# Generated deterministically by seda-macro-lef-normalizer-v1; recipe orfs-asap7-fakeram-m4-v1.
VERSION 5.8 ;
BUSBITCHARS "[]" ;
DIVIDERCHAR "/" ;

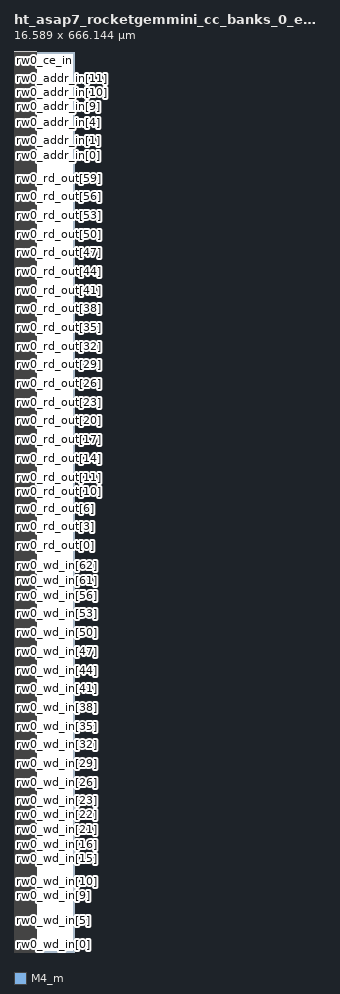
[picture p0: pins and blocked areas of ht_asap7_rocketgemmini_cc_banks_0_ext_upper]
MACRO ht_asap7_rocketgemmini_cc_banks_0_ext_upper
  FOREIGN ht_asap7_rocketgemmini_cc_banks_0_ext_upper 0 0 ;
  CLASS COVER ;
  ORIGIN 0 0 ;
  SIZE 16.589 BY 666.144 ;
  SYMMETRY X Y R90 ;
  PIN rw0_wd_in[0]
    DIRECTION INPUT ;
    USE SIGNAL ;
    SHAPE ABUTMENT ;
    PORT
      LAYER M4_m ;
      RECT 0 0.048 0.024 0.072 ;
    END
  END rw0_wd_in[0]
  PIN rw0_wd_in[1]
    DIRECTION INPUT ;
    USE SIGNAL ;
    SHAPE ABUTMENT ;
    PORT
      LAYER M4_m ;
      RECT 0 4.656 0.024 4.68 ;
    END
  END rw0_wd_in[1]
  PIN rw0_wd_in[2]
    DIRECTION INPUT ;
    USE SIGNAL ;
    SHAPE ABUTMENT ;
    PORT
      LAYER M4_m ;
      RECT 0 9.264 0.024 9.288 ;
    END
  END rw0_wd_in[2]
  PIN rw0_wd_in[3]
    DIRECTION INPUT ;
    USE SIGNAL ;
    SHAPE ABUTMENT ;
    PORT
      LAYER M4_m ;
      RECT 0 13.872 0.024 13.896 ;
    END
  END rw0_wd_in[3]
  PIN rw0_wd_in[4]
    DIRECTION INPUT ;
    USE SIGNAL ;
    SHAPE ABUTMENT ;
    PORT
      LAYER M4_m ;
      RECT 0 18.48 0.024 18.504 ;
    END
  END rw0_wd_in[4]
  PIN rw0_wd_in[5]
    DIRECTION INPUT ;
    USE SIGNAL ;
    SHAPE ABUTMENT ;
    PORT
      LAYER M4_m ;
      RECT 0 23.088 0.024 23.112 ;
    END
  END rw0_wd_in[5]
  PIN rw0_wd_in[6]
    DIRECTION INPUT ;
    USE SIGNAL ;
    SHAPE ABUTMENT ;
    PORT
      LAYER M4_m ;
      RECT 0 27.696 0.024 27.72 ;
    END
  END rw0_wd_in[6]
  PIN rw0_wd_in[7]
    DIRECTION INPUT ;
    USE SIGNAL ;
    SHAPE ABUTMENT ;
    PORT
      LAYER M4_m ;
      RECT 0 32.304 0.024 32.328 ;
    END
  END rw0_wd_in[7]
  PIN rw0_wd_in[8]
    DIRECTION INPUT ;
    USE SIGNAL ;
    SHAPE ABUTMENT ;
    PORT
      LAYER M4_m ;
      RECT 0 36.912 0.024 36.936 ;
    END
  END rw0_wd_in[8]
  PIN rw0_wd_in[9]
    DIRECTION INPUT ;
    USE SIGNAL ;
    SHAPE ABUTMENT ;
    PORT
      LAYER M4_m ;
      RECT 0 41.52 0.024 41.544 ;
    END
  END rw0_wd_in[9]
  PIN rw0_wd_in[10]
    DIRECTION INPUT ;
    USE SIGNAL ;
    SHAPE ABUTMENT ;
    PORT
      LAYER M4_m ;
      RECT 0 46.128 0.024 46.152 ;
    END
  END rw0_wd_in[10]
  PIN rw0_wd_in[11]
    DIRECTION INPUT ;
    USE SIGNAL ;
    SHAPE ABUTMENT ;
    PORT
      LAYER M4_m ;
      RECT 0 50.736 0.024 50.76 ;
    END
  END rw0_wd_in[11]
  PIN rw0_wd_in[12]
    DIRECTION INPUT ;
    USE SIGNAL ;
    SHAPE ABUTMENT ;
    PORT
      LAYER M4_m ;
      RECT 0 55.344 0.024 55.368 ;
    END
  END rw0_wd_in[12]
  PIN rw0_wd_in[13]
    DIRECTION INPUT ;
    USE SIGNAL ;
    SHAPE ABUTMENT ;
    PORT
      LAYER M4_m ;
      RECT 0 59.952 0.024 59.976 ;
    END
  END rw0_wd_in[13]
  PIN rw0_wd_in[14]
    DIRECTION INPUT ;
    USE SIGNAL ;
    SHAPE ABUTMENT ;
    PORT
      LAYER M4_m ;
      RECT 0 64.56 0.024 64.584 ;
    END
  END rw0_wd_in[14]
  PIN rw0_wd_in[15]
    DIRECTION INPUT ;
    USE SIGNAL ;
    SHAPE ABUTMENT ;
    PORT
      LAYER M4_m ;
      RECT 0 69.168 0.024 69.192 ;
    END
  END rw0_wd_in[15]
  PIN rw0_wd_in[16]
    DIRECTION INPUT ;
    USE SIGNAL ;
    SHAPE ABUTMENT ;
    PORT
      LAYER M4_m ;
      RECT 0 73.776 0.024 73.8 ;
    END
  END rw0_wd_in[16]
  PIN rw0_wd_in[17]
    DIRECTION INPUT ;
    USE SIGNAL ;
    SHAPE ABUTMENT ;
    PORT
      LAYER M4_m ;
      RECT 0 78.384 0.024 78.408 ;
    END
  END rw0_wd_in[17]
  PIN rw0_wd_in[18]
    DIRECTION INPUT ;
    USE SIGNAL ;
    SHAPE ABUTMENT ;
    PORT
      LAYER M4_m ;
      RECT 0 82.992 0.024 83.016 ;
    END
  END rw0_wd_in[18]
  PIN rw0_wd_in[19]
    DIRECTION INPUT ;
    USE SIGNAL ;
    SHAPE ABUTMENT ;
    PORT
      LAYER M4_m ;
      RECT 0 87.6 0.024 87.624 ;
    END
  END rw0_wd_in[19]
  PIN rw0_wd_in[20]
    DIRECTION INPUT ;
    USE SIGNAL ;
    SHAPE ABUTMENT ;
    PORT
      LAYER M4_m ;
      RECT 0 92.208 0.024 92.232 ;
    END
  END rw0_wd_in[20]
  PIN rw0_wd_in[21]
    DIRECTION INPUT ;
    USE SIGNAL ;
    SHAPE ABUTMENT ;
    PORT
      LAYER M4_m ;
      RECT 0 96.816 0.024 96.84 ;
    END
  END rw0_wd_in[21]
  PIN rw0_wd_in[22]
    DIRECTION INPUT ;
    USE SIGNAL ;
    SHAPE ABUTMENT ;
    PORT
      LAYER M4_m ;
      RECT 0 101.424 0.024 101.448 ;
    END
  END rw0_wd_in[22]
  PIN rw0_wd_in[23]
    DIRECTION INPUT ;
    USE SIGNAL ;
    SHAPE ABUTMENT ;
    PORT
      LAYER M4_m ;
      RECT 0 106.032 0.024 106.056 ;
    END
  END rw0_wd_in[23]
  PIN rw0_wd_in[24]
    DIRECTION INPUT ;
    USE SIGNAL ;
    SHAPE ABUTMENT ;
    PORT
      LAYER M4_m ;
      RECT 0 110.64 0.024 110.664 ;
    END
  END rw0_wd_in[24]
  PIN rw0_wd_in[25]
    DIRECTION INPUT ;
    USE SIGNAL ;
    SHAPE ABUTMENT ;
    PORT
      LAYER M4_m ;
      RECT 0 115.248 0.024 115.272 ;
    END
  END rw0_wd_in[25]
  PIN rw0_wd_in[26]
    DIRECTION INPUT ;
    USE SIGNAL ;
    SHAPE ABUTMENT ;
    PORT
      LAYER M4_m ;
      RECT 0 119.856 0.024 119.88 ;
    END
  END rw0_wd_in[26]
  PIN rw0_wd_in[27]
    DIRECTION INPUT ;
    USE SIGNAL ;
    SHAPE ABUTMENT ;
    PORT
      LAYER M4_m ;
      RECT 0 124.464 0.024 124.488 ;
    END
  END rw0_wd_in[27]
  PIN rw0_wd_in[28]
    DIRECTION INPUT ;
    USE SIGNAL ;
    SHAPE ABUTMENT ;
    PORT
      LAYER M4_m ;
      RECT 0 129.072 0.024 129.096 ;
    END
  END rw0_wd_in[28]
  PIN rw0_wd_in[29]
    DIRECTION INPUT ;
    USE SIGNAL ;
    SHAPE ABUTMENT ;
    PORT
      LAYER M4_m ;
      RECT 0 133.68 0.024 133.704 ;
    END
  END rw0_wd_in[29]
  PIN rw0_wd_in[30]
    DIRECTION INPUT ;
    USE SIGNAL ;
    SHAPE ABUTMENT ;
    PORT
      LAYER M4_m ;
      RECT 0 138.288 0.024 138.312 ;
    END
  END rw0_wd_in[30]
  PIN rw0_wd_in[31]
    DIRECTION INPUT ;
    USE SIGNAL ;
    SHAPE ABUTMENT ;
    PORT
      LAYER M4_m ;
      RECT 0 142.896 0.024 142.92 ;
    END
  END rw0_wd_in[31]
  PIN rw0_wd_in[32]
    DIRECTION INPUT ;
    USE SIGNAL ;
    SHAPE ABUTMENT ;
    PORT
      LAYER M4_m ;
      RECT 0 147.504 0.024 147.528 ;
    END
  END rw0_wd_in[32]
  PIN rw0_wd_in[33]
    DIRECTION INPUT ;
    USE SIGNAL ;
    SHAPE ABUTMENT ;
    PORT
      LAYER M4_m ;
      RECT 0 152.112 0.024 152.136 ;
    END
  END rw0_wd_in[33]
  PIN rw0_wd_in[34]
    DIRECTION INPUT ;
    USE SIGNAL ;
    SHAPE ABUTMENT ;
    PORT
      LAYER M4_m ;
      RECT 0 156.72 0.024 156.744 ;
    END
  END rw0_wd_in[34]
  PIN rw0_wd_in[35]
    DIRECTION INPUT ;
    USE SIGNAL ;
    SHAPE ABUTMENT ;
    PORT
      LAYER M4_m ;
      RECT 0 161.328 0.024 161.352 ;
    END
  END rw0_wd_in[35]
  PIN rw0_wd_in[36]
    DIRECTION INPUT ;
    USE SIGNAL ;
    SHAPE ABUTMENT ;
    PORT
      LAYER M4_m ;
      RECT 0 165.936 0.024 165.96 ;
    END
  END rw0_wd_in[36]
  PIN rw0_wd_in[37]
    DIRECTION INPUT ;
    USE SIGNAL ;
    SHAPE ABUTMENT ;
    PORT
      LAYER M4_m ;
      RECT 0 170.544 0.024 170.568 ;
    END
  END rw0_wd_in[37]
  PIN rw0_wd_in[38]
    DIRECTION INPUT ;
    USE SIGNAL ;
    SHAPE ABUTMENT ;
    PORT
      LAYER M4_m ;
      RECT 0 175.152 0.024 175.176 ;
    END
  END rw0_wd_in[38]
  PIN rw0_wd_in[39]
    DIRECTION INPUT ;
    USE SIGNAL ;
    SHAPE ABUTMENT ;
    PORT
      LAYER M4_m ;
      RECT 0 179.76 0.024 179.784 ;
    END
  END rw0_wd_in[39]
  PIN rw0_wd_in[40]
    DIRECTION INPUT ;
    USE SIGNAL ;
    SHAPE ABUTMENT ;
    PORT
      LAYER M4_m ;
      RECT 0 184.368 0.024 184.392 ;
    END
  END rw0_wd_in[40]
  PIN rw0_wd_in[41]
    DIRECTION INPUT ;
    USE SIGNAL ;
    SHAPE ABUTMENT ;
    PORT
      LAYER M4_m ;
      RECT 0 188.976 0.024 189 ;
    END
  END rw0_wd_in[41]
  PIN rw0_wd_in[42]
    DIRECTION INPUT ;
    USE SIGNAL ;
    SHAPE ABUTMENT ;
    PORT
      LAYER M4_m ;
      RECT 0 193.584 0.024 193.608 ;
    END
  END rw0_wd_in[42]
  PIN rw0_wd_in[43]
    DIRECTION INPUT ;
    USE SIGNAL ;
    SHAPE ABUTMENT ;
    PORT
      LAYER M4_m ;
      RECT 0 198.192 0.024 198.216 ;
    END
  END rw0_wd_in[43]
  PIN rw0_wd_in[44]
    DIRECTION INPUT ;
    USE SIGNAL ;
    SHAPE ABUTMENT ;
    PORT
      LAYER M4_m ;
      RECT 0 202.8 0.024 202.824 ;
    END
  END rw0_wd_in[44]
  PIN rw0_wd_in[45]
    DIRECTION INPUT ;
    USE SIGNAL ;
    SHAPE ABUTMENT ;
    PORT
      LAYER M4_m ;
      RECT 0 207.408 0.024 207.432 ;
    END
  END rw0_wd_in[45]
  PIN rw0_wd_in[46]
    DIRECTION INPUT ;
    USE SIGNAL ;
    SHAPE ABUTMENT ;
    PORT
      LAYER M4_m ;
      RECT 0 212.016 0.024 212.04 ;
    END
  END rw0_wd_in[46]
  PIN rw0_wd_in[47]
    DIRECTION INPUT ;
    USE SIGNAL ;
    SHAPE ABUTMENT ;
    PORT
      LAYER M4_m ;
      RECT 0 216.624 0.024 216.648 ;
    END
  END rw0_wd_in[47]
  PIN rw0_wd_in[48]
    DIRECTION INPUT ;
    USE SIGNAL ;
    SHAPE ABUTMENT ;
    PORT
      LAYER M4_m ;
      RECT 0 221.232 0.024 221.256 ;
    END
  END rw0_wd_in[48]
  PIN rw0_wd_in[49]
    DIRECTION INPUT ;
    USE SIGNAL ;
    SHAPE ABUTMENT ;
    PORT
      LAYER M4_m ;
      RECT 0 225.84 0.024 225.864 ;
    END
  END rw0_wd_in[49]
  PIN rw0_wd_in[50]
    DIRECTION INPUT ;
    USE SIGNAL ;
    SHAPE ABUTMENT ;
    PORT
      LAYER M4_m ;
      RECT 0 230.448 0.024 230.472 ;
    END
  END rw0_wd_in[50]
  PIN rw0_wd_in[51]
    DIRECTION INPUT ;
    USE SIGNAL ;
    SHAPE ABUTMENT ;
    PORT
      LAYER M4_m ;
      RECT 0 235.056 0.024 235.08 ;
    END
  END rw0_wd_in[51]
  PIN rw0_wd_in[52]
    DIRECTION INPUT ;
    USE SIGNAL ;
    SHAPE ABUTMENT ;
    PORT
      LAYER M4_m ;
      RECT 0 239.664 0.024 239.688 ;
    END
  END rw0_wd_in[52]
  PIN rw0_wd_in[53]
    DIRECTION INPUT ;
    USE SIGNAL ;
    SHAPE ABUTMENT ;
    PORT
      LAYER M4_m ;
      RECT 0 244.272 0.024 244.296 ;
    END
  END rw0_wd_in[53]
  PIN rw0_wd_in[54]
    DIRECTION INPUT ;
    USE SIGNAL ;
    SHAPE ABUTMENT ;
    PORT
      LAYER M4_m ;
      RECT 0 248.88 0.024 248.904 ;
    END
  END rw0_wd_in[54]
  PIN rw0_wd_in[55]
    DIRECTION INPUT ;
    USE SIGNAL ;
    SHAPE ABUTMENT ;
    PORT
      LAYER M4_m ;
      RECT 0 253.488 0.024 253.512 ;
    END
  END rw0_wd_in[55]
  PIN rw0_wd_in[56]
    DIRECTION INPUT ;
    USE SIGNAL ;
    SHAPE ABUTMENT ;
    PORT
      LAYER M4_m ;
      RECT 0 258.096 0.024 258.12 ;
    END
  END rw0_wd_in[56]
  PIN rw0_wd_in[57]
    DIRECTION INPUT ;
    USE SIGNAL ;
    SHAPE ABUTMENT ;
    PORT
      LAYER M4_m ;
      RECT 0 262.704 0.024 262.728 ;
    END
  END rw0_wd_in[57]
  PIN rw0_wd_in[58]
    DIRECTION INPUT ;
    USE SIGNAL ;
    SHAPE ABUTMENT ;
    PORT
      LAYER M4_m ;
      RECT 0 267.312 0.024 267.336 ;
    END
  END rw0_wd_in[58]
  PIN rw0_wd_in[59]
    DIRECTION INPUT ;
    USE SIGNAL ;
    SHAPE ABUTMENT ;
    PORT
      LAYER M4_m ;
      RECT 0 271.92 0.024 271.944 ;
    END
  END rw0_wd_in[59]
  PIN rw0_wd_in[60]
    DIRECTION INPUT ;
    USE SIGNAL ;
    SHAPE ABUTMENT ;
    PORT
      LAYER M4_m ;
      RECT 0 276.528 0.024 276.552 ;
    END
  END rw0_wd_in[60]
  PIN rw0_wd_in[61]
    DIRECTION INPUT ;
    USE SIGNAL ;
    SHAPE ABUTMENT ;
    PORT
      LAYER M4_m ;
      RECT 0 281.136 0.024 281.16 ;
    END
  END rw0_wd_in[61]
  PIN rw0_wd_in[62]
    DIRECTION INPUT ;
    USE SIGNAL ;
    SHAPE ABUTMENT ;
    PORT
      LAYER M4_m ;
      RECT 0 285.744 0.024 285.768 ;
    END
  END rw0_wd_in[62]
  PIN rw0_wd_in[63]
    DIRECTION INPUT ;
    USE SIGNAL ;
    SHAPE ABUTMENT ;
    PORT
      LAYER M4_m ;
      RECT 0 290.352 0.024 290.376 ;
    END
  END rw0_wd_in[63]
  PIN rw0_rd_out[0]
    DIRECTION OUTPUT ;
    USE SIGNAL ;
    SHAPE ABUTMENT ;
    PORT
      LAYER M4_m ;
      RECT 0 294.96 0.024 294.984 ;
    END
  END rw0_rd_out[0]
  PIN rw0_rd_out[1]
    DIRECTION OUTPUT ;
    USE SIGNAL ;
    SHAPE ABUTMENT ;
    PORT
      LAYER M4_m ;
      RECT 0 299.568 0.024 299.592 ;
    END
  END rw0_rd_out[1]
  PIN rw0_rd_out[2]
    DIRECTION OUTPUT ;
    USE SIGNAL ;
    SHAPE ABUTMENT ;
    PORT
      LAYER M4_m ;
      RECT 0 304.176 0.024 304.2 ;
    END
  END rw0_rd_out[2]
  PIN rw0_rd_out[3]
    DIRECTION OUTPUT ;
    USE SIGNAL ;
    SHAPE ABUTMENT ;
    PORT
      LAYER M4_m ;
      RECT 0 308.784 0.024 308.808 ;
    END
  END rw0_rd_out[3]
  PIN rw0_rd_out[4]
    DIRECTION OUTPUT ;
    USE SIGNAL ;
    SHAPE ABUTMENT ;
    PORT
      LAYER M4_m ;
      RECT 0 313.392 0.024 313.416 ;
    END
  END rw0_rd_out[4]
  PIN rw0_rd_out[5]
    DIRECTION OUTPUT ;
    USE SIGNAL ;
    SHAPE ABUTMENT ;
    PORT
      LAYER M4_m ;
      RECT 0 318 0.024 318.024 ;
    END
  END rw0_rd_out[5]
  PIN rw0_rd_out[6]
    DIRECTION OUTPUT ;
    USE SIGNAL ;
    SHAPE ABUTMENT ;
    PORT
      LAYER M4_m ;
      RECT 0 322.608 0.024 322.632 ;
    END
  END rw0_rd_out[6]
  PIN rw0_rd_out[7]
    DIRECTION OUTPUT ;
    USE SIGNAL ;
    SHAPE ABUTMENT ;
    PORT
      LAYER M4_m ;
      RECT 0 327.216 0.024 327.24 ;
    END
  END rw0_rd_out[7]
  PIN rw0_rd_out[8]
    DIRECTION OUTPUT ;
    USE SIGNAL ;
    SHAPE ABUTMENT ;
    PORT
      LAYER M4_m ;
      RECT 0 331.824 0.024 331.848 ;
    END
  END rw0_rd_out[8]
  PIN rw0_rd_out[9]
    DIRECTION OUTPUT ;
    USE SIGNAL ;
    SHAPE ABUTMENT ;
    PORT
      LAYER M4_m ;
      RECT 0 336.432 0.024 336.456 ;
    END
  END rw0_rd_out[9]
  PIN rw0_rd_out[10]
    DIRECTION OUTPUT ;
    USE SIGNAL ;
    SHAPE ABUTMENT ;
    PORT
      LAYER M4_m ;
      RECT 0 341.04 0.024 341.064 ;
    END
  END rw0_rd_out[10]
  PIN rw0_rd_out[11]
    DIRECTION OUTPUT ;
    USE SIGNAL ;
    SHAPE ABUTMENT ;
    PORT
      LAYER M4_m ;
      RECT 0 345.648 0.024 345.672 ;
    END
  END rw0_rd_out[11]
  PIN rw0_rd_out[12]
    DIRECTION OUTPUT ;
    USE SIGNAL ;
    SHAPE ABUTMENT ;
    PORT
      LAYER M4_m ;
      RECT 0 350.256 0.024 350.28 ;
    END
  END rw0_rd_out[12]
  PIN rw0_rd_out[13]
    DIRECTION OUTPUT ;
    USE SIGNAL ;
    SHAPE ABUTMENT ;
    PORT
      LAYER M4_m ;
      RECT 0 354.864 0.024 354.888 ;
    END
  END rw0_rd_out[13]
  PIN rw0_rd_out[14]
    DIRECTION OUTPUT ;
    USE SIGNAL ;
    SHAPE ABUTMENT ;
    PORT
      LAYER M4_m ;
      RECT 0 359.472 0.024 359.496 ;
    END
  END rw0_rd_out[14]
  PIN rw0_rd_out[15]
    DIRECTION OUTPUT ;
    USE SIGNAL ;
    SHAPE ABUTMENT ;
    PORT
      LAYER M4_m ;
      RECT 0 364.08 0.024 364.104 ;
    END
  END rw0_rd_out[15]
  PIN rw0_rd_out[16]
    DIRECTION OUTPUT ;
    USE SIGNAL ;
    SHAPE ABUTMENT ;
    PORT
      LAYER M4_m ;
      RECT 0 368.688 0.024 368.712 ;
    END
  END rw0_rd_out[16]
  PIN rw0_rd_out[17]
    DIRECTION OUTPUT ;
    USE SIGNAL ;
    SHAPE ABUTMENT ;
    PORT
      LAYER M4_m ;
      RECT 0 373.296 0.024 373.32 ;
    END
  END rw0_rd_out[17]
  PIN rw0_rd_out[18]
    DIRECTION OUTPUT ;
    USE SIGNAL ;
    SHAPE ABUTMENT ;
    PORT
      LAYER M4_m ;
      RECT 0 377.904 0.024 377.928 ;
    END
  END rw0_rd_out[18]
  PIN rw0_rd_out[19]
    DIRECTION OUTPUT ;
    USE SIGNAL ;
    SHAPE ABUTMENT ;
    PORT
      LAYER M4_m ;
      RECT 0 382.512 0.024 382.536 ;
    END
  END rw0_rd_out[19]
  PIN rw0_rd_out[20]
    DIRECTION OUTPUT ;
    USE SIGNAL ;
    SHAPE ABUTMENT ;
    PORT
      LAYER M4_m ;
      RECT 0 387.12 0.024 387.144 ;
    END
  END rw0_rd_out[20]
  PIN rw0_rd_out[21]
    DIRECTION OUTPUT ;
    USE SIGNAL ;
    SHAPE ABUTMENT ;
    PORT
      LAYER M4_m ;
      RECT 0 391.728 0.024 391.752 ;
    END
  END rw0_rd_out[21]
  PIN rw0_rd_out[22]
    DIRECTION OUTPUT ;
    USE SIGNAL ;
    SHAPE ABUTMENT ;
    PORT
      LAYER M4_m ;
      RECT 0 396.336 0.024 396.36 ;
    END
  END rw0_rd_out[22]
  PIN rw0_rd_out[23]
    DIRECTION OUTPUT ;
    USE SIGNAL ;
    SHAPE ABUTMENT ;
    PORT
      LAYER M4_m ;
      RECT 0 400.944 0.024 400.968 ;
    END
  END rw0_rd_out[23]
  PIN rw0_rd_out[24]
    DIRECTION OUTPUT ;
    USE SIGNAL ;
    SHAPE ABUTMENT ;
    PORT
      LAYER M4_m ;
      RECT 0 405.552 0.024 405.576 ;
    END
  END rw0_rd_out[24]
  PIN rw0_rd_out[25]
    DIRECTION OUTPUT ;
    USE SIGNAL ;
    SHAPE ABUTMENT ;
    PORT
      LAYER M4_m ;
      RECT 0 410.16 0.024 410.184 ;
    END
  END rw0_rd_out[25]
  PIN rw0_rd_out[26]
    DIRECTION OUTPUT ;
    USE SIGNAL ;
    SHAPE ABUTMENT ;
    PORT
      LAYER M4_m ;
      RECT 0 414.768 0.024 414.792 ;
    END
  END rw0_rd_out[26]
  PIN rw0_rd_out[27]
    DIRECTION OUTPUT ;
    USE SIGNAL ;
    SHAPE ABUTMENT ;
    PORT
      LAYER M4_m ;
      RECT 0 419.376 0.024 419.4 ;
    END
  END rw0_rd_out[27]
  PIN rw0_rd_out[28]
    DIRECTION OUTPUT ;
    USE SIGNAL ;
    SHAPE ABUTMENT ;
    PORT
      LAYER M4_m ;
      RECT 0 423.984 0.024 424.008 ;
    END
  END rw0_rd_out[28]
  PIN rw0_rd_out[29]
    DIRECTION OUTPUT ;
    USE SIGNAL ;
    SHAPE ABUTMENT ;
    PORT
      LAYER M4_m ;
      RECT 0 428.592 0.024 428.616 ;
    END
  END rw0_rd_out[29]
  PIN rw0_rd_out[30]
    DIRECTION OUTPUT ;
    USE SIGNAL ;
    SHAPE ABUTMENT ;
    PORT
      LAYER M4_m ;
      RECT 0 433.2 0.024 433.224 ;
    END
  END rw0_rd_out[30]
  PIN rw0_rd_out[31]
    DIRECTION OUTPUT ;
    USE SIGNAL ;
    SHAPE ABUTMENT ;
    PORT
      LAYER M4_m ;
      RECT 0 437.808 0.024 437.832 ;
    END
  END rw0_rd_out[31]
  PIN rw0_rd_out[32]
    DIRECTION OUTPUT ;
    USE SIGNAL ;
    SHAPE ABUTMENT ;
    PORT
      LAYER M4_m ;
      RECT 0 442.416 0.024 442.44 ;
    END
  END rw0_rd_out[32]
  PIN rw0_rd_out[33]
    DIRECTION OUTPUT ;
    USE SIGNAL ;
    SHAPE ABUTMENT ;
    PORT
      LAYER M4_m ;
      RECT 0 447.024 0.024 447.048 ;
    END
  END rw0_rd_out[33]
  PIN rw0_rd_out[34]
    DIRECTION OUTPUT ;
    USE SIGNAL ;
    SHAPE ABUTMENT ;
    PORT
      LAYER M4_m ;
      RECT 0 451.632 0.024 451.656 ;
    END
  END rw0_rd_out[34]
  PIN rw0_rd_out[35]
    DIRECTION OUTPUT ;
    USE SIGNAL ;
    SHAPE ABUTMENT ;
    PORT
      LAYER M4_m ;
      RECT 0 456.24 0.024 456.264 ;
    END
  END rw0_rd_out[35]
  PIN rw0_rd_out[36]
    DIRECTION OUTPUT ;
    USE SIGNAL ;
    SHAPE ABUTMENT ;
    PORT
      LAYER M4_m ;
      RECT 0 460.848 0.024 460.872 ;
    END
  END rw0_rd_out[36]
  PIN rw0_rd_out[37]
    DIRECTION OUTPUT ;
    USE SIGNAL ;
    SHAPE ABUTMENT ;
    PORT
      LAYER M4_m ;
      RECT 0 465.456 0.024 465.48 ;
    END
  END rw0_rd_out[37]
  PIN rw0_rd_out[38]
    DIRECTION OUTPUT ;
    USE SIGNAL ;
    SHAPE ABUTMENT ;
    PORT
      LAYER M4_m ;
      RECT 0 470.064 0.024 470.088 ;
    END
  END rw0_rd_out[38]
  PIN rw0_rd_out[39]
    DIRECTION OUTPUT ;
    USE SIGNAL ;
    SHAPE ABUTMENT ;
    PORT
      LAYER M4_m ;
      RECT 0 474.672 0.024 474.696 ;
    END
  END rw0_rd_out[39]
  PIN rw0_rd_out[40]
    DIRECTION OUTPUT ;
    USE SIGNAL ;
    SHAPE ABUTMENT ;
    PORT
      LAYER M4_m ;
      RECT 0 479.28 0.024 479.304 ;
    END
  END rw0_rd_out[40]
  PIN rw0_rd_out[41]
    DIRECTION OUTPUT ;
    USE SIGNAL ;
    SHAPE ABUTMENT ;
    PORT
      LAYER M4_m ;
      RECT 0 483.888 0.024 483.912 ;
    END
  END rw0_rd_out[41]
  PIN rw0_rd_out[42]
    DIRECTION OUTPUT ;
    USE SIGNAL ;
    SHAPE ABUTMENT ;
    PORT
      LAYER M4_m ;
      RECT 0 488.496 0.024 488.52 ;
    END
  END rw0_rd_out[42]
  PIN rw0_rd_out[43]
    DIRECTION OUTPUT ;
    USE SIGNAL ;
    SHAPE ABUTMENT ;
    PORT
      LAYER M4_m ;
      RECT 0 493.104 0.024 493.128 ;
    END
  END rw0_rd_out[43]
  PIN rw0_rd_out[44]
    DIRECTION OUTPUT ;
    USE SIGNAL ;
    SHAPE ABUTMENT ;
    PORT
      LAYER M4_m ;
      RECT 0 497.712 0.024 497.736 ;
    END
  END rw0_rd_out[44]
  PIN rw0_rd_out[45]
    DIRECTION OUTPUT ;
    USE SIGNAL ;
    SHAPE ABUTMENT ;
    PORT
      LAYER M4_m ;
      RECT 0 502.32 0.024 502.344 ;
    END
  END rw0_rd_out[45]
  PIN rw0_rd_out[46]
    DIRECTION OUTPUT ;
    USE SIGNAL ;
    SHAPE ABUTMENT ;
    PORT
      LAYER M4_m ;
      RECT 0 506.928 0.024 506.952 ;
    END
  END rw0_rd_out[46]
  PIN rw0_rd_out[47]
    DIRECTION OUTPUT ;
    USE SIGNAL ;
    SHAPE ABUTMENT ;
    PORT
      LAYER M4_m ;
      RECT 0 511.536 0.024 511.56 ;
    END
  END rw0_rd_out[47]
  PIN rw0_rd_out[48]
    DIRECTION OUTPUT ;
    USE SIGNAL ;
    SHAPE ABUTMENT ;
    PORT
      LAYER M4_m ;
      RECT 0 516.144 0.024 516.168 ;
    END
  END rw0_rd_out[48]
  PIN rw0_rd_out[49]
    DIRECTION OUTPUT ;
    USE SIGNAL ;
    SHAPE ABUTMENT ;
    PORT
      LAYER M4_m ;
      RECT 0 520.752 0.024 520.776 ;
    END
  END rw0_rd_out[49]
  PIN rw0_rd_out[50]
    DIRECTION OUTPUT ;
    USE SIGNAL ;
    SHAPE ABUTMENT ;
    PORT
      LAYER M4_m ;
      RECT 0 525.36 0.024 525.384 ;
    END
  END rw0_rd_out[50]
  PIN rw0_rd_out[51]
    DIRECTION OUTPUT ;
    USE SIGNAL ;
    SHAPE ABUTMENT ;
    PORT
      LAYER M4_m ;
      RECT 0 529.968 0.024 529.992 ;
    END
  END rw0_rd_out[51]
  PIN rw0_rd_out[52]
    DIRECTION OUTPUT ;
    USE SIGNAL ;
    SHAPE ABUTMENT ;
    PORT
      LAYER M4_m ;
      RECT 0 534.576 0.024 534.6 ;
    END
  END rw0_rd_out[52]
  PIN rw0_rd_out[53]
    DIRECTION OUTPUT ;
    USE SIGNAL ;
    SHAPE ABUTMENT ;
    PORT
      LAYER M4_m ;
      RECT 0 539.184 0.024 539.208 ;
    END
  END rw0_rd_out[53]
  PIN rw0_rd_out[54]
    DIRECTION OUTPUT ;
    USE SIGNAL ;
    SHAPE ABUTMENT ;
    PORT
      LAYER M4_m ;
      RECT 0 543.792 0.024 543.816 ;
    END
  END rw0_rd_out[54]
  PIN rw0_rd_out[55]
    DIRECTION OUTPUT ;
    USE SIGNAL ;
    SHAPE ABUTMENT ;
    PORT
      LAYER M4_m ;
      RECT 0 548.4 0.024 548.424 ;
    END
  END rw0_rd_out[55]
  PIN rw0_rd_out[56]
    DIRECTION OUTPUT ;
    USE SIGNAL ;
    SHAPE ABUTMENT ;
    PORT
      LAYER M4_m ;
      RECT 0 553.008 0.024 553.032 ;
    END
  END rw0_rd_out[56]
  PIN rw0_rd_out[57]
    DIRECTION OUTPUT ;
    USE SIGNAL ;
    SHAPE ABUTMENT ;
    PORT
      LAYER M4_m ;
      RECT 0 557.616 0.024 557.64 ;
    END
  END rw0_rd_out[57]
  PIN rw0_rd_out[58]
    DIRECTION OUTPUT ;
    USE SIGNAL ;
    SHAPE ABUTMENT ;
    PORT
      LAYER M4_m ;
      RECT 0 562.224 0.024 562.248 ;
    END
  END rw0_rd_out[58]
  PIN rw0_rd_out[59]
    DIRECTION OUTPUT ;
    USE SIGNAL ;
    SHAPE ABUTMENT ;
    PORT
      LAYER M4_m ;
      RECT 0 566.832 0.024 566.856 ;
    END
  END rw0_rd_out[59]
  PIN rw0_rd_out[60]
    DIRECTION OUTPUT ;
    USE SIGNAL ;
    SHAPE ABUTMENT ;
    PORT
      LAYER M4_m ;
      RECT 0 571.44 0.024 571.464 ;
    END
  END rw0_rd_out[60]
  PIN rw0_rd_out[61]
    DIRECTION OUTPUT ;
    USE SIGNAL ;
    SHAPE ABUTMENT ;
    PORT
      LAYER M4_m ;
      RECT 0 576.048 0.024 576.072 ;
    END
  END rw0_rd_out[61]
  PIN rw0_rd_out[62]
    DIRECTION OUTPUT ;
    USE SIGNAL ;
    SHAPE ABUTMENT ;
    PORT
      LAYER M4_m ;
      RECT 0 580.656 0.024 580.68 ;
    END
  END rw0_rd_out[62]
  PIN rw0_rd_out[63]
    DIRECTION OUTPUT ;
    USE SIGNAL ;
    SHAPE ABUTMENT ;
    PORT
      LAYER M4_m ;
      RECT 0 585.264 0.024 585.288 ;
    END
  END rw0_rd_out[63]
  PIN rw0_addr_in[0]
    DIRECTION INPUT ;
    USE SIGNAL ;
    SHAPE ABUTMENT ;
    PORT
      LAYER M4_m ;
      RECT 0 589.872 0.024 589.896 ;
    END
  END rw0_addr_in[0]
  PIN rw0_addr_in[1]
    DIRECTION INPUT ;
    USE SIGNAL ;
    SHAPE ABUTMENT ;
    PORT
      LAYER M4_m ;
      RECT 0 594.48 0.024 594.504 ;
    END
  END rw0_addr_in[1]
  PIN rw0_addr_in[2]
    DIRECTION INPUT ;
    USE SIGNAL ;
    SHAPE ABUTMENT ;
    PORT
      LAYER M4_m ;
      RECT 0 599.088 0.024 599.112 ;
    END
  END rw0_addr_in[2]
  PIN rw0_addr_in[3]
    DIRECTION INPUT ;
    USE SIGNAL ;
    SHAPE ABUTMENT ;
    PORT
      LAYER M4_m ;
      RECT 0 603.696 0.024 603.72 ;
    END
  END rw0_addr_in[3]
  PIN rw0_addr_in[4]
    DIRECTION INPUT ;
    USE SIGNAL ;
    SHAPE ABUTMENT ;
    PORT
      LAYER M4_m ;
      RECT 0 608.304 0.024 608.328 ;
    END
  END rw0_addr_in[4]
  PIN rw0_addr_in[5]
    DIRECTION INPUT ;
    USE SIGNAL ;
    SHAPE ABUTMENT ;
    PORT
      LAYER M4_m ;
      RECT 0 612.912 0.024 612.936 ;
    END
  END rw0_addr_in[5]
  PIN rw0_addr_in[6]
    DIRECTION INPUT ;
    USE SIGNAL ;
    SHAPE ABUTMENT ;
    PORT
      LAYER M4_m ;
      RECT 0 617.52 0.024 617.544 ;
    END
  END rw0_addr_in[6]
  PIN rw0_addr_in[7]
    DIRECTION INPUT ;
    USE SIGNAL ;
    SHAPE ABUTMENT ;
    PORT
      LAYER M4_m ;
      RECT 0 622.128 0.024 622.152 ;
    END
  END rw0_addr_in[7]
  PIN rw0_addr_in[8]
    DIRECTION INPUT ;
    USE SIGNAL ;
    SHAPE ABUTMENT ;
    PORT
      LAYER M4_m ;
      RECT 0 626.736 0.024 626.76 ;
    END
  END rw0_addr_in[8]
  PIN rw0_addr_in[9]
    DIRECTION INPUT ;
    USE SIGNAL ;
    SHAPE ABUTMENT ;
    PORT
      LAYER M4_m ;
      RECT 0 631.344 0.024 631.368 ;
    END
  END rw0_addr_in[9]
  PIN rw0_addr_in[10]
    DIRECTION INPUT ;
    USE SIGNAL ;
    SHAPE ABUTMENT ;
    PORT
      LAYER M4_m ;
      RECT 0 635.952 0.024 635.976 ;
    END
  END rw0_addr_in[10]
  PIN rw0_addr_in[11]
    DIRECTION INPUT ;
    USE SIGNAL ;
    SHAPE ABUTMENT ;
    PORT
      LAYER M4_m ;
      RECT 0 640.56 0.024 640.584 ;
    END
  END rw0_addr_in[11]
  PIN rw0_addr_in[12]
    DIRECTION INPUT ;
    USE SIGNAL ;
    SHAPE ABUTMENT ;
    PORT
      LAYER M4_m ;
      RECT 0 645.168 0.024 645.192 ;
    END
  END rw0_addr_in[12]
  PIN rw0_we_in
    DIRECTION INPUT ;
    USE SIGNAL ;
    SHAPE ABUTMENT ;
    PORT
      LAYER M4_m ;
      RECT 0 649.776 0.024 649.8 ;
    END
  END rw0_we_in
  PIN rw0_ce_in
    DIRECTION INPUT ;
    USE SIGNAL ;
    SHAPE ABUTMENT ;
    PORT
      LAYER M4_m ;
      RECT 0 654.384 0.024 654.408 ;
    END
  END rw0_ce_in
  PIN rw0_clk
    DIRECTION INPUT ;
    USE SIGNAL ;
    SHAPE ABUTMENT ;
    PORT
      LAYER M4_m ;
      RECT 0 658.992 0.024 659.016 ;
    END
  END rw0_clk
  PIN VSS
    DIRECTION INOUT ;
    USE GROUND ;
    PORT
      LAYER M4_m ;
      RECT 0.048 0 16.541 0.096 ;
      RECT 0.048 0.768 16.541 0.864 ;
      RECT 0.048 1.536 16.541 1.632 ;
      RECT 0.048 2.304 16.541 2.4 ;
      RECT 0.048 3.072 16.541 3.168 ;
      RECT 0.048 3.84 16.541 3.936 ;
      RECT 0.048 4.608 16.541 4.704 ;
      RECT 0.048 5.376 16.541 5.472 ;
      RECT 0.048 6.144 16.541 6.24 ;
      RECT 0.048 6.912 16.541 7.008 ;
      RECT 0.048 7.68 16.541 7.776 ;
      RECT 0.048 8.448 16.541 8.544 ;
      RECT 0.048 9.216 16.541 9.312 ;
      RECT 0.048 9.984 16.541 10.08 ;
      RECT 0.048 10.752 16.541 10.848 ;
      RECT 0.048 11.52 16.541 11.616 ;
      RECT 0.048 12.288 16.541 12.384 ;
      RECT 0.048 13.056 16.541 13.152 ;
      RECT 0.048 13.824 16.541 13.92 ;
      RECT 0.048 14.592 16.541 14.688 ;
      RECT 0.048 15.36 16.541 15.456 ;
      RECT 0.048 16.128 16.541 16.224 ;
      RECT 0.048 16.896 16.541 16.992 ;
      RECT 0.048 17.664 16.541 17.76 ;
      RECT 0.048 18.432 16.541 18.528 ;
      RECT 0.048 19.2 16.541 19.296 ;
      RECT 0.048 19.968 16.541 20.064 ;
      RECT 0.048 20.736 16.541 20.832 ;
      RECT 0.048 21.504 16.541 21.6 ;
      RECT 0.048 22.272 16.541 22.368 ;
      RECT 0.048 23.04 16.541 23.136 ;
      RECT 0.048 23.808 16.541 23.904 ;
      RECT 0.048 24.576 16.541 24.672 ;
      RECT 0.048 25.344 16.541 25.44 ;
      RECT 0.048 26.112 16.541 26.208 ;
      RECT 0.048 26.88 16.541 26.976 ;
      RECT 0.048 27.648 16.541 27.744 ;
      RECT 0.048 28.416 16.541 28.512 ;
      RECT 0.048 29.184 16.541 29.28 ;
      RECT 0.048 29.952 16.541 30.048 ;
      RECT 0.048 30.72 16.541 30.816 ;
      RECT 0.048 31.488 16.541 31.584 ;
      RECT 0.048 32.256 16.541 32.352 ;
      RECT 0.048 33.024 16.541 33.12 ;
      RECT 0.048 33.792 16.541 33.888 ;
      RECT 0.048 34.56 16.541 34.656 ;
      RECT 0.048 35.328 16.541 35.424 ;
      RECT 0.048 36.096 16.541 36.192 ;
      RECT 0.048 36.864 16.541 36.96 ;
      RECT 0.048 37.632 16.541 37.728 ;
      RECT 0.048 38.4 16.541 38.496 ;
      RECT 0.048 39.168 16.541 39.264 ;
      RECT 0.048 39.936 16.541 40.032 ;
      RECT 0.048 40.704 16.541 40.8 ;
      RECT 0.048 41.472 16.541 41.568 ;
      RECT 0.048 42.24 16.541 42.336 ;
      RECT 0.048 43.008 16.541 43.104 ;
      RECT 0.048 43.776 16.541 43.872 ;
      RECT 0.048 44.544 16.541 44.64 ;
      RECT 0.048 45.312 16.541 45.408 ;
      RECT 0.048 46.08 16.541 46.176 ;
      RECT 0.048 46.848 16.541 46.944 ;
      RECT 0.048 47.616 16.541 47.712 ;
      RECT 0.048 48.384 16.541 48.48 ;
      RECT 0.048 49.152 16.541 49.248 ;
      RECT 0.048 49.92 16.541 50.016 ;
      RECT 0.048 50.688 16.541 50.784 ;
      RECT 0.048 51.456 16.541 51.552 ;
      RECT 0.048 52.224 16.541 52.32 ;
      RECT 0.048 52.992 16.541 53.088 ;
      RECT 0.048 53.76 16.541 53.856 ;
      RECT 0.048 54.528 16.541 54.624 ;
      RECT 0.048 55.296 16.541 55.392 ;
      RECT 0.048 56.064 16.541 56.16 ;
      RECT 0.048 56.832 16.541 56.928 ;
      RECT 0.048 57.6 16.541 57.696 ;
      RECT 0.048 58.368 16.541 58.464 ;
      RECT 0.048 59.136 16.541 59.232 ;
      RECT 0.048 59.904 16.541 60 ;
      RECT 0.048 60.672 16.541 60.768 ;
      RECT 0.048 61.44 16.541 61.536 ;
      RECT 0.048 62.208 16.541 62.304 ;
      RECT 0.048 62.976 16.541 63.072 ;
      RECT 0.048 63.744 16.541 63.84 ;
      RECT 0.048 64.512 16.541 64.608 ;
      RECT 0.048 65.28 16.541 65.376 ;
      RECT 0.048 66.048 16.541 66.144 ;
      RECT 0.048 66.816 16.541 66.912 ;
      RECT 0.048 67.584 16.541 67.68 ;
      RECT 0.048 68.352 16.541 68.448 ;
      RECT 0.048 69.12 16.541 69.216 ;
      RECT 0.048 69.888 16.541 69.984 ;
      RECT 0.048 70.656 16.541 70.752 ;
      RECT 0.048 71.424 16.541 71.52 ;
      RECT 0.048 72.192 16.541 72.288 ;
      RECT 0.048 72.96 16.541 73.056 ;
      RECT 0.048 73.728 16.541 73.824 ;
      RECT 0.048 74.496 16.541 74.592 ;
      RECT 0.048 75.264 16.541 75.36 ;
      RECT 0.048 76.032 16.541 76.128 ;
      RECT 0.048 76.8 16.541 76.896 ;
      RECT 0.048 77.568 16.541 77.664 ;
      RECT 0.048 78.336 16.541 78.432 ;
      RECT 0.048 79.104 16.541 79.2 ;
      RECT 0.048 79.872 16.541 79.968 ;
      RECT 0.048 80.64 16.541 80.736 ;
      RECT 0.048 81.408 16.541 81.504 ;
      RECT 0.048 82.176 16.541 82.272 ;
      RECT 0.048 82.944 16.541 83.04 ;
      RECT 0.048 83.712 16.541 83.808 ;
      RECT 0.048 84.48 16.541 84.576 ;
      RECT 0.048 85.248 16.541 85.344 ;
      RECT 0.048 86.016 16.541 86.112 ;
      RECT 0.048 86.784 16.541 86.88 ;
      RECT 0.048 87.552 16.541 87.648 ;
      RECT 0.048 88.32 16.541 88.416 ;
      RECT 0.048 89.088 16.541 89.184 ;
      RECT 0.048 89.856 16.541 89.952 ;
      RECT 0.048 90.624 16.541 90.72 ;
      RECT 0.048 91.392 16.541 91.488 ;
      RECT 0.048 92.16 16.541 92.256 ;
      RECT 0.048 92.928 16.541 93.024 ;
      RECT 0.048 93.696 16.541 93.792 ;
      RECT 0.048 94.464 16.541 94.56 ;
      RECT 0.048 95.232 16.541 95.328 ;
      RECT 0.048 96 16.541 96.096 ;
      RECT 0.048 96.768 16.541 96.864 ;
      RECT 0.048 97.536 16.541 97.632 ;
      RECT 0.048 98.304 16.541 98.4 ;
      RECT 0.048 99.072 16.541 99.168 ;
      RECT 0.048 99.84 16.541 99.936 ;
      RECT 0.048 100.608 16.541 100.704 ;
      RECT 0.048 101.376 16.541 101.472 ;
      RECT 0.048 102.144 16.541 102.24 ;
      RECT 0.048 102.912 16.541 103.008 ;
      RECT 0.048 103.68 16.541 103.776 ;
      RECT 0.048 104.448 16.541 104.544 ;
      RECT 0.048 105.216 16.541 105.312 ;
      RECT 0.048 105.984 16.541 106.08 ;
      RECT 0.048 106.752 16.541 106.848 ;
      RECT 0.048 107.52 16.541 107.616 ;
      RECT 0.048 108.288 16.541 108.384 ;
      RECT 0.048 109.056 16.541 109.152 ;
      RECT 0.048 109.824 16.541 109.92 ;
      RECT 0.048 110.592 16.541 110.688 ;
      RECT 0.048 111.36 16.541 111.456 ;
      RECT 0.048 112.128 16.541 112.224 ;
      RECT 0.048 112.896 16.541 112.992 ;
      RECT 0.048 113.664 16.541 113.76 ;
      RECT 0.048 114.432 16.541 114.528 ;
      RECT 0.048 115.2 16.541 115.296 ;
      RECT 0.048 115.968 16.541 116.064 ;
      RECT 0.048 116.736 16.541 116.832 ;
      RECT 0.048 117.504 16.541 117.6 ;
      RECT 0.048 118.272 16.541 118.368 ;
      RECT 0.048 119.04 16.541 119.136 ;
      RECT 0.048 119.808 16.541 119.904 ;
      RECT 0.048 120.576 16.541 120.672 ;
      RECT 0.048 121.344 16.541 121.44 ;
      RECT 0.048 122.112 16.541 122.208 ;
      RECT 0.048 122.88 16.541 122.976 ;
      RECT 0.048 123.648 16.541 123.744 ;
      RECT 0.048 124.416 16.541 124.512 ;
      RECT 0.048 125.184 16.541 125.28 ;
      RECT 0.048 125.952 16.541 126.048 ;
      RECT 0.048 126.72 16.541 126.816 ;
      RECT 0.048 127.488 16.541 127.584 ;
      RECT 0.048 128.256 16.541 128.352 ;
      RECT 0.048 129.024 16.541 129.12 ;
      RECT 0.048 129.792 16.541 129.888 ;
      RECT 0.048 130.56 16.541 130.656 ;
      RECT 0.048 131.328 16.541 131.424 ;
      RECT 0.048 132.096 16.541 132.192 ;
      RECT 0.048 132.864 16.541 132.96 ;
      RECT 0.048 133.632 16.541 133.728 ;
      RECT 0.048 134.4 16.541 134.496 ;
      RECT 0.048 135.168 16.541 135.264 ;
      RECT 0.048 135.936 16.541 136.032 ;
      RECT 0.048 136.704 16.541 136.8 ;
      RECT 0.048 137.472 16.541 137.568 ;
      RECT 0.048 138.24 16.541 138.336 ;
      RECT 0.048 139.008 16.541 139.104 ;
      RECT 0.048 139.776 16.541 139.872 ;
      RECT 0.048 140.544 16.541 140.64 ;
      RECT 0.048 141.312 16.541 141.408 ;
      RECT 0.048 142.08 16.541 142.176 ;
      RECT 0.048 142.848 16.541 142.944 ;
      RECT 0.048 143.616 16.541 143.712 ;
      RECT 0.048 144.384 16.541 144.48 ;
      RECT 0.048 145.152 16.541 145.248 ;
      RECT 0.048 145.92 16.541 146.016 ;
      RECT 0.048 146.688 16.541 146.784 ;
      RECT 0.048 147.456 16.541 147.552 ;
      RECT 0.048 148.224 16.541 148.32 ;
      RECT 0.048 148.992 16.541 149.088 ;
      RECT 0.048 149.76 16.541 149.856 ;
      RECT 0.048 150.528 16.541 150.624 ;
      RECT 0.048 151.296 16.541 151.392 ;
      RECT 0.048 152.064 16.541 152.16 ;
      RECT 0.048 152.832 16.541 152.928 ;
      RECT 0.048 153.6 16.541 153.696 ;
      RECT 0.048 154.368 16.541 154.464 ;
      RECT 0.048 155.136 16.541 155.232 ;
      RECT 0.048 155.904 16.541 156 ;
      RECT 0.048 156.672 16.541 156.768 ;
      RECT 0.048 157.44 16.541 157.536 ;
      RECT 0.048 158.208 16.541 158.304 ;
      RECT 0.048 158.976 16.541 159.072 ;
      RECT 0.048 159.744 16.541 159.84 ;
      RECT 0.048 160.512 16.541 160.608 ;
      RECT 0.048 161.28 16.541 161.376 ;
      RECT 0.048 162.048 16.541 162.144 ;
      RECT 0.048 162.816 16.541 162.912 ;
      RECT 0.048 163.584 16.541 163.68 ;
      RECT 0.048 164.352 16.541 164.448 ;
      RECT 0.048 165.12 16.541 165.216 ;
      RECT 0.048 165.888 16.541 165.984 ;
      RECT 0.048 166.656 16.541 166.752 ;
      RECT 0.048 167.424 16.541 167.52 ;
      RECT 0.048 168.192 16.541 168.288 ;
      RECT 0.048 168.96 16.541 169.056 ;
      RECT 0.048 169.728 16.541 169.824 ;
      RECT 0.048 170.496 16.541 170.592 ;
      RECT 0.048 171.264 16.541 171.36 ;
      RECT 0.048 172.032 16.541 172.128 ;
      RECT 0.048 172.8 16.541 172.896 ;
      RECT 0.048 173.568 16.541 173.664 ;
      RECT 0.048 174.336 16.541 174.432 ;
      RECT 0.048 175.104 16.541 175.2 ;
      RECT 0.048 175.872 16.541 175.968 ;
      RECT 0.048 176.64 16.541 176.736 ;
      RECT 0.048 177.408 16.541 177.504 ;
      RECT 0.048 178.176 16.541 178.272 ;
      RECT 0.048 178.944 16.541 179.04 ;
      RECT 0.048 179.712 16.541 179.808 ;
      RECT 0.048 180.48 16.541 180.576 ;
      RECT 0.048 181.248 16.541 181.344 ;
      RECT 0.048 182.016 16.541 182.112 ;
      RECT 0.048 182.784 16.541 182.88 ;
      RECT 0.048 183.552 16.541 183.648 ;
      RECT 0.048 184.32 16.541 184.416 ;
      RECT 0.048 185.088 16.541 185.184 ;
      RECT 0.048 185.856 16.541 185.952 ;
      RECT 0.048 186.624 16.541 186.72 ;
      RECT 0.048 187.392 16.541 187.488 ;
      RECT 0.048 188.16 16.541 188.256 ;
      RECT 0.048 188.928 16.541 189.024 ;
      RECT 0.048 189.696 16.541 189.792 ;
      RECT 0.048 190.464 16.541 190.56 ;
      RECT 0.048 191.232 16.541 191.328 ;
      RECT 0.048 192 16.541 192.096 ;
      RECT 0.048 192.768 16.541 192.864 ;
      RECT 0.048 193.536 16.541 193.632 ;
      RECT 0.048 194.304 16.541 194.4 ;
      RECT 0.048 195.072 16.541 195.168 ;
      RECT 0.048 195.84 16.541 195.936 ;
      RECT 0.048 196.608 16.541 196.704 ;
      RECT 0.048 197.376 16.541 197.472 ;
      RECT 0.048 198.144 16.541 198.24 ;
      RECT 0.048 198.912 16.541 199.008 ;
      RECT 0.048 199.68 16.541 199.776 ;
      RECT 0.048 200.448 16.541 200.544 ;
      RECT 0.048 201.216 16.541 201.312 ;
      RECT 0.048 201.984 16.541 202.08 ;
      RECT 0.048 202.752 16.541 202.848 ;
      RECT 0.048 203.52 16.541 203.616 ;
      RECT 0.048 204.288 16.541 204.384 ;
      RECT 0.048 205.056 16.541 205.152 ;
      RECT 0.048 205.824 16.541 205.92 ;
      RECT 0.048 206.592 16.541 206.688 ;
      RECT 0.048 207.36 16.541 207.456 ;
      RECT 0.048 208.128 16.541 208.224 ;
      RECT 0.048 208.896 16.541 208.992 ;
      RECT 0.048 209.664 16.541 209.76 ;
      RECT 0.048 210.432 16.541 210.528 ;
      RECT 0.048 211.2 16.541 211.296 ;
      RECT 0.048 211.968 16.541 212.064 ;
      RECT 0.048 212.736 16.541 212.832 ;
      RECT 0.048 213.504 16.541 213.6 ;
      RECT 0.048 214.272 16.541 214.368 ;
      RECT 0.048 215.04 16.541 215.136 ;
      RECT 0.048 215.808 16.541 215.904 ;
      RECT 0.048 216.576 16.541 216.672 ;
      RECT 0.048 217.344 16.541 217.44 ;
      RECT 0.048 218.112 16.541 218.208 ;
      RECT 0.048 218.88 16.541 218.976 ;
      RECT 0.048 219.648 16.541 219.744 ;
      RECT 0.048 220.416 16.541 220.512 ;
      RECT 0.048 221.184 16.541 221.28 ;
      RECT 0.048 221.952 16.541 222.048 ;
      RECT 0.048 222.72 16.541 222.816 ;
      RECT 0.048 223.488 16.541 223.584 ;
      RECT 0.048 224.256 16.541 224.352 ;
      RECT 0.048 225.024 16.541 225.12 ;
      RECT 0.048 225.792 16.541 225.888 ;
      RECT 0.048 226.56 16.541 226.656 ;
      RECT 0.048 227.328 16.541 227.424 ;
      RECT 0.048 228.096 16.541 228.192 ;
      RECT 0.048 228.864 16.541 228.96 ;
      RECT 0.048 229.632 16.541 229.728 ;
      RECT 0.048 230.4 16.541 230.496 ;
      RECT 0.048 231.168 16.541 231.264 ;
      RECT 0.048 231.936 16.541 232.032 ;
      RECT 0.048 232.704 16.541 232.8 ;
      RECT 0.048 233.472 16.541 233.568 ;
      RECT 0.048 234.24 16.541 234.336 ;
      RECT 0.048 235.008 16.541 235.104 ;
      RECT 0.048 235.776 16.541 235.872 ;
      RECT 0.048 236.544 16.541 236.64 ;
      RECT 0.048 237.312 16.541 237.408 ;
      RECT 0.048 238.08 16.541 238.176 ;
      RECT 0.048 238.848 16.541 238.944 ;
      RECT 0.048 239.616 16.541 239.712 ;
      RECT 0.048 240.384 16.541 240.48 ;
      RECT 0.048 241.152 16.541 241.248 ;
      RECT 0.048 241.92 16.541 242.016 ;
      RECT 0.048 242.688 16.541 242.784 ;
      RECT 0.048 243.456 16.541 243.552 ;
      RECT 0.048 244.224 16.541 244.32 ;
      RECT 0.048 244.992 16.541 245.088 ;
      RECT 0.048 245.76 16.541 245.856 ;
      RECT 0.048 246.528 16.541 246.624 ;
      RECT 0.048 247.296 16.541 247.392 ;
      RECT 0.048 248.064 16.541 248.16 ;
      RECT 0.048 248.832 16.541 248.928 ;
      RECT 0.048 249.6 16.541 249.696 ;
      RECT 0.048 250.368 16.541 250.464 ;
      RECT 0.048 251.136 16.541 251.232 ;
      RECT 0.048 251.904 16.541 252 ;
      RECT 0.048 252.672 16.541 252.768 ;
      RECT 0.048 253.44 16.541 253.536 ;
      RECT 0.048 254.208 16.541 254.304 ;
      RECT 0.048 254.976 16.541 255.072 ;
      RECT 0.048 255.744 16.541 255.84 ;
      RECT 0.048 256.512 16.541 256.608 ;
      RECT 0.048 257.28 16.541 257.376 ;
      RECT 0.048 258.048 16.541 258.144 ;
      RECT 0.048 258.816 16.541 258.912 ;
      RECT 0.048 259.584 16.541 259.68 ;
      RECT 0.048 260.352 16.541 260.448 ;
      RECT 0.048 261.12 16.541 261.216 ;
      RECT 0.048 261.888 16.541 261.984 ;
      RECT 0.048 262.656 16.541 262.752 ;
      RECT 0.048 263.424 16.541 263.52 ;
      RECT 0.048 264.192 16.541 264.288 ;
      RECT 0.048 264.96 16.541 265.056 ;
      RECT 0.048 265.728 16.541 265.824 ;
      RECT 0.048 266.496 16.541 266.592 ;
      RECT 0.048 267.264 16.541 267.36 ;
      RECT 0.048 268.032 16.541 268.128 ;
      RECT 0.048 268.8 16.541 268.896 ;
      RECT 0.048 269.568 16.541 269.664 ;
      RECT 0.048 270.336 16.541 270.432 ;
      RECT 0.048 271.104 16.541 271.2 ;
      RECT 0.048 271.872 16.541 271.968 ;
      RECT 0.048 272.64 16.541 272.736 ;
      RECT 0.048 273.408 16.541 273.504 ;
      RECT 0.048 274.176 16.541 274.272 ;
      RECT 0.048 274.944 16.541 275.04 ;
      RECT 0.048 275.712 16.541 275.808 ;
      RECT 0.048 276.48 16.541 276.576 ;
      RECT 0.048 277.248 16.541 277.344 ;
      RECT 0.048 278.016 16.541 278.112 ;
      RECT 0.048 278.784 16.541 278.88 ;
      RECT 0.048 279.552 16.541 279.648 ;
      RECT 0.048 280.32 16.541 280.416 ;
      RECT 0.048 281.088 16.541 281.184 ;
      RECT 0.048 281.856 16.541 281.952 ;
      RECT 0.048 282.624 16.541 282.72 ;
      RECT 0.048 283.392 16.541 283.488 ;
      RECT 0.048 284.16 16.541 284.256 ;
      RECT 0.048 284.928 16.541 285.024 ;
      RECT 0.048 285.696 16.541 285.792 ;
      RECT 0.048 286.464 16.541 286.56 ;
      RECT 0.048 287.232 16.541 287.328 ;
      RECT 0.048 288 16.541 288.096 ;
      RECT 0.048 288.768 16.541 288.864 ;
      RECT 0.048 289.536 16.541 289.632 ;
      RECT 0.048 290.304 16.541 290.4 ;
      RECT 0.048 291.072 16.541 291.168 ;
      RECT 0.048 291.84 16.541 291.936 ;
      RECT 0.048 292.608 16.541 292.704 ;
      RECT 0.048 293.376 16.541 293.472 ;
      RECT 0.048 294.144 16.541 294.24 ;
      RECT 0.048 294.912 16.541 295.008 ;
      RECT 0.048 295.68 16.541 295.776 ;
      RECT 0.048 296.448 16.541 296.544 ;
      RECT 0.048 297.216 16.541 297.312 ;
      RECT 0.048 297.984 16.541 298.08 ;
      RECT 0.048 298.752 16.541 298.848 ;
      RECT 0.048 299.52 16.541 299.616 ;
      RECT 0.048 300.288 16.541 300.384 ;
      RECT 0.048 301.056 16.541 301.152 ;
      RECT 0.048 301.824 16.541 301.92 ;
      RECT 0.048 302.592 16.541 302.688 ;
      RECT 0.048 303.36 16.541 303.456 ;
      RECT 0.048 304.128 16.541 304.224 ;
      RECT 0.048 304.896 16.541 304.992 ;
      RECT 0.048 305.664 16.541 305.76 ;
      RECT 0.048 306.432 16.541 306.528 ;
      RECT 0.048 307.2 16.541 307.296 ;
      RECT 0.048 307.968 16.541 308.064 ;
      RECT 0.048 308.736 16.541 308.832 ;
      RECT 0.048 309.504 16.541 309.6 ;
      RECT 0.048 310.272 16.541 310.368 ;
      RECT 0.048 311.04 16.541 311.136 ;
      RECT 0.048 311.808 16.541 311.904 ;
      RECT 0.048 312.576 16.541 312.672 ;
      RECT 0.048 313.344 16.541 313.44 ;
      RECT 0.048 314.112 16.541 314.208 ;
      RECT 0.048 314.88 16.541 314.976 ;
      RECT 0.048 315.648 16.541 315.744 ;
      RECT 0.048 316.416 16.541 316.512 ;
      RECT 0.048 317.184 16.541 317.28 ;
      RECT 0.048 317.952 16.541 318.048 ;
      RECT 0.048 318.72 16.541 318.816 ;
      RECT 0.048 319.488 16.541 319.584 ;
      RECT 0.048 320.256 16.541 320.352 ;
      RECT 0.048 321.024 16.541 321.12 ;
      RECT 0.048 321.792 16.541 321.888 ;
      RECT 0.048 322.56 16.541 322.656 ;
      RECT 0.048 323.328 16.541 323.424 ;
      RECT 0.048 324.096 16.541 324.192 ;
      RECT 0.048 324.864 16.541 324.96 ;
      RECT 0.048 325.632 16.541 325.728 ;
      RECT 0.048 326.4 16.541 326.496 ;
      RECT 0.048 327.168 16.541 327.264 ;
      RECT 0.048 327.936 16.541 328.032 ;
      RECT 0.048 328.704 16.541 328.8 ;
      RECT 0.048 329.472 16.541 329.568 ;
      RECT 0.048 330.24 16.541 330.336 ;
      RECT 0.048 331.008 16.541 331.104 ;
      RECT 0.048 331.776 16.541 331.872 ;
      RECT 0.048 332.544 16.541 332.64 ;
      RECT 0.048 333.312 16.541 333.408 ;
      RECT 0.048 334.08 16.541 334.176 ;
      RECT 0.048 334.848 16.541 334.944 ;
      RECT 0.048 335.616 16.541 335.712 ;
      RECT 0.048 336.384 16.541 336.48 ;
      RECT 0.048 337.152 16.541 337.248 ;
      RECT 0.048 337.92 16.541 338.016 ;
      RECT 0.048 338.688 16.541 338.784 ;
      RECT 0.048 339.456 16.541 339.552 ;
      RECT 0.048 340.224 16.541 340.32 ;
      RECT 0.048 340.992 16.541 341.088 ;
      RECT 0.048 341.76 16.541 341.856 ;
      RECT 0.048 342.528 16.541 342.624 ;
      RECT 0.048 343.296 16.541 343.392 ;
      RECT 0.048 344.064 16.541 344.16 ;
      RECT 0.048 344.832 16.541 344.928 ;
      RECT 0.048 345.6 16.541 345.696 ;
      RECT 0.048 346.368 16.541 346.464 ;
      RECT 0.048 347.136 16.541 347.232 ;
      RECT 0.048 347.904 16.541 348 ;
      RECT 0.048 348.672 16.541 348.768 ;
      RECT 0.048 349.44 16.541 349.536 ;
      RECT 0.048 350.208 16.541 350.304 ;
      RECT 0.048 350.976 16.541 351.072 ;
      RECT 0.048 351.744 16.541 351.84 ;
      RECT 0.048 352.512 16.541 352.608 ;
      RECT 0.048 353.28 16.541 353.376 ;
      RECT 0.048 354.048 16.541 354.144 ;
      RECT 0.048 354.816 16.541 354.912 ;
      RECT 0.048 355.584 16.541 355.68 ;
      RECT 0.048 356.352 16.541 356.448 ;
      RECT 0.048 357.12 16.541 357.216 ;
      RECT 0.048 357.888 16.541 357.984 ;
      RECT 0.048 358.656 16.541 358.752 ;
      RECT 0.048 359.424 16.541 359.52 ;
      RECT 0.048 360.192 16.541 360.288 ;
      RECT 0.048 360.96 16.541 361.056 ;
      RECT 0.048 361.728 16.541 361.824 ;
      RECT 0.048 362.496 16.541 362.592 ;
      RECT 0.048 363.264 16.541 363.36 ;
      RECT 0.048 364.032 16.541 364.128 ;
      RECT 0.048 364.8 16.541 364.896 ;
      RECT 0.048 365.568 16.541 365.664 ;
      RECT 0.048 366.336 16.541 366.432 ;
      RECT 0.048 367.104 16.541 367.2 ;
      RECT 0.048 367.872 16.541 367.968 ;
      RECT 0.048 368.64 16.541 368.736 ;
      RECT 0.048 369.408 16.541 369.504 ;
      RECT 0.048 370.176 16.541 370.272 ;
      RECT 0.048 370.944 16.541 371.04 ;
      RECT 0.048 371.712 16.541 371.808 ;
      RECT 0.048 372.48 16.541 372.576 ;
      RECT 0.048 373.248 16.541 373.344 ;
      RECT 0.048 374.016 16.541 374.112 ;
      RECT 0.048 374.784 16.541 374.88 ;
      RECT 0.048 375.552 16.541 375.648 ;
      RECT 0.048 376.32 16.541 376.416 ;
      RECT 0.048 377.088 16.541 377.184 ;
      RECT 0.048 377.856 16.541 377.952 ;
      RECT 0.048 378.624 16.541 378.72 ;
      RECT 0.048 379.392 16.541 379.488 ;
      RECT 0.048 380.16 16.541 380.256 ;
      RECT 0.048 380.928 16.541 381.024 ;
      RECT 0.048 381.696 16.541 381.792 ;
      RECT 0.048 382.464 16.541 382.56 ;
      RECT 0.048 383.232 16.541 383.328 ;
      RECT 0.048 384 16.541 384.096 ;
      RECT 0.048 384.768 16.541 384.864 ;
      RECT 0.048 385.536 16.541 385.632 ;
      RECT 0.048 386.304 16.541 386.4 ;
      RECT 0.048 387.072 16.541 387.168 ;
      RECT 0.048 387.84 16.541 387.936 ;
      RECT 0.048 388.608 16.541 388.704 ;
      RECT 0.048 389.376 16.541 389.472 ;
      RECT 0.048 390.144 16.541 390.24 ;
      RECT 0.048 390.912 16.541 391.008 ;
      RECT 0.048 391.68 16.541 391.776 ;
      RECT 0.048 392.448 16.541 392.544 ;
      RECT 0.048 393.216 16.541 393.312 ;
      RECT 0.048 393.984 16.541 394.08 ;
      RECT 0.048 394.752 16.541 394.848 ;
      RECT 0.048 395.52 16.541 395.616 ;
      RECT 0.048 396.288 16.541 396.384 ;
      RECT 0.048 397.056 16.541 397.152 ;
      RECT 0.048 397.824 16.541 397.92 ;
      RECT 0.048 398.592 16.541 398.688 ;
      RECT 0.048 399.36 16.541 399.456 ;
      RECT 0.048 400.128 16.541 400.224 ;
      RECT 0.048 400.896 16.541 400.992 ;
      RECT 0.048 401.664 16.541 401.76 ;
      RECT 0.048 402.432 16.541 402.528 ;
      RECT 0.048 403.2 16.541 403.296 ;
      RECT 0.048 403.968 16.541 404.064 ;
      RECT 0.048 404.736 16.541 404.832 ;
      RECT 0.048 405.504 16.541 405.6 ;
      RECT 0.048 406.272 16.541 406.368 ;
      RECT 0.048 407.04 16.541 407.136 ;
      RECT 0.048 407.808 16.541 407.904 ;
      RECT 0.048 408.576 16.541 408.672 ;
      RECT 0.048 409.344 16.541 409.44 ;
      RECT 0.048 410.112 16.541 410.208 ;
      RECT 0.048 410.88 16.541 410.976 ;
      RECT 0.048 411.648 16.541 411.744 ;
      RECT 0.048 412.416 16.541 412.512 ;
      RECT 0.048 413.184 16.541 413.28 ;
      RECT 0.048 413.952 16.541 414.048 ;
      RECT 0.048 414.72 16.541 414.816 ;
      RECT 0.048 415.488 16.541 415.584 ;
      RECT 0.048 416.256 16.541 416.352 ;
      RECT 0.048 417.024 16.541 417.12 ;
      RECT 0.048 417.792 16.541 417.888 ;
      RECT 0.048 418.56 16.541 418.656 ;
      RECT 0.048 419.328 16.541 419.424 ;
      RECT 0.048 420.096 16.541 420.192 ;
      RECT 0.048 420.864 16.541 420.96 ;
      RECT 0.048 421.632 16.541 421.728 ;
      RECT 0.048 422.4 16.541 422.496 ;
      RECT 0.048 423.168 16.541 423.264 ;
      RECT 0.048 423.936 16.541 424.032 ;
      RECT 0.048 424.704 16.541 424.8 ;
      RECT 0.048 425.472 16.541 425.568 ;
      RECT 0.048 426.24 16.541 426.336 ;
      RECT 0.048 427.008 16.541 427.104 ;
      RECT 0.048 427.776 16.541 427.872 ;
      RECT 0.048 428.544 16.541 428.64 ;
      RECT 0.048 429.312 16.541 429.408 ;
      RECT 0.048 430.08 16.541 430.176 ;
      RECT 0.048 430.848 16.541 430.944 ;
      RECT 0.048 431.616 16.541 431.712 ;
      RECT 0.048 432.384 16.541 432.48 ;
      RECT 0.048 433.152 16.541 433.248 ;
      RECT 0.048 433.92 16.541 434.016 ;
      RECT 0.048 434.688 16.541 434.784 ;
      RECT 0.048 435.456 16.541 435.552 ;
      RECT 0.048 436.224 16.541 436.32 ;
      RECT 0.048 436.992 16.541 437.088 ;
      RECT 0.048 437.76 16.541 437.856 ;
      RECT 0.048 438.528 16.541 438.624 ;
      RECT 0.048 439.296 16.541 439.392 ;
      RECT 0.048 440.064 16.541 440.16 ;
      RECT 0.048 440.832 16.541 440.928 ;
      RECT 0.048 441.6 16.541 441.696 ;
      RECT 0.048 442.368 16.541 442.464 ;
      RECT 0.048 443.136 16.541 443.232 ;
      RECT 0.048 443.904 16.541 444 ;
      RECT 0.048 444.672 16.541 444.768 ;
      RECT 0.048 445.44 16.541 445.536 ;
      RECT 0.048 446.208 16.541 446.304 ;
      RECT 0.048 446.976 16.541 447.072 ;
      RECT 0.048 447.744 16.541 447.84 ;
      RECT 0.048 448.512 16.541 448.608 ;
      RECT 0.048 449.28 16.541 449.376 ;
      RECT 0.048 450.048 16.541 450.144 ;
      RECT 0.048 450.816 16.541 450.912 ;
      RECT 0.048 451.584 16.541 451.68 ;
      RECT 0.048 452.352 16.541 452.448 ;
      RECT 0.048 453.12 16.541 453.216 ;
      RECT 0.048 453.888 16.541 453.984 ;
      RECT 0.048 454.656 16.541 454.752 ;
      RECT 0.048 455.424 16.541 455.52 ;
      RECT 0.048 456.192 16.541 456.288 ;
      RECT 0.048 456.96 16.541 457.056 ;
      RECT 0.048 457.728 16.541 457.824 ;
      RECT 0.048 458.496 16.541 458.592 ;
      RECT 0.048 459.264 16.541 459.36 ;
      RECT 0.048 460.032 16.541 460.128 ;
      RECT 0.048 460.8 16.541 460.896 ;
      RECT 0.048 461.568 16.541 461.664 ;
      RECT 0.048 462.336 16.541 462.432 ;
      RECT 0.048 463.104 16.541 463.2 ;
      RECT 0.048 463.872 16.541 463.968 ;
      RECT 0.048 464.64 16.541 464.736 ;
      RECT 0.048 465.408 16.541 465.504 ;
      RECT 0.048 466.176 16.541 466.272 ;
      RECT 0.048 466.944 16.541 467.04 ;
      RECT 0.048 467.712 16.541 467.808 ;
      RECT 0.048 468.48 16.541 468.576 ;
      RECT 0.048 469.248 16.541 469.344 ;
      RECT 0.048 470.016 16.541 470.112 ;
      RECT 0.048 470.784 16.541 470.88 ;
      RECT 0.048 471.552 16.541 471.648 ;
      RECT 0.048 472.32 16.541 472.416 ;
      RECT 0.048 473.088 16.541 473.184 ;
      RECT 0.048 473.856 16.541 473.952 ;
      RECT 0.048 474.624 16.541 474.72 ;
      RECT 0.048 475.392 16.541 475.488 ;
      RECT 0.048 476.16 16.541 476.256 ;
      RECT 0.048 476.928 16.541 477.024 ;
      RECT 0.048 477.696 16.541 477.792 ;
      RECT 0.048 478.464 16.541 478.56 ;
      RECT 0.048 479.232 16.541 479.328 ;
      RECT 0.048 480 16.541 480.096 ;
      RECT 0.048 480.768 16.541 480.864 ;
      RECT 0.048 481.536 16.541 481.632 ;
      RECT 0.048 482.304 16.541 482.4 ;
      RECT 0.048 483.072 16.541 483.168 ;
      RECT 0.048 483.84 16.541 483.936 ;
      RECT 0.048 484.608 16.541 484.704 ;
      RECT 0.048 485.376 16.541 485.472 ;
      RECT 0.048 486.144 16.541 486.24 ;
      RECT 0.048 486.912 16.541 487.008 ;
      RECT 0.048 487.68 16.541 487.776 ;
      RECT 0.048 488.448 16.541 488.544 ;
      RECT 0.048 489.216 16.541 489.312 ;
      RECT 0.048 489.984 16.541 490.08 ;
      RECT 0.048 490.752 16.541 490.848 ;
      RECT 0.048 491.52 16.541 491.616 ;
      RECT 0.048 492.288 16.541 492.384 ;
      RECT 0.048 493.056 16.541 493.152 ;
      RECT 0.048 493.824 16.541 493.92 ;
      RECT 0.048 494.592 16.541 494.688 ;
      RECT 0.048 495.36 16.541 495.456 ;
      RECT 0.048 496.128 16.541 496.224 ;
      RECT 0.048 496.896 16.541 496.992 ;
      RECT 0.048 497.664 16.541 497.76 ;
      RECT 0.048 498.432 16.541 498.528 ;
      RECT 0.048 499.2 16.541 499.296 ;
      RECT 0.048 499.968 16.541 500.064 ;
      RECT 0.048 500.736 16.541 500.832 ;
      RECT 0.048 501.504 16.541 501.6 ;
      RECT 0.048 502.272 16.541 502.368 ;
      RECT 0.048 503.04 16.541 503.136 ;
      RECT 0.048 503.808 16.541 503.904 ;
      RECT 0.048 504.576 16.541 504.672 ;
      RECT 0.048 505.344 16.541 505.44 ;
      RECT 0.048 506.112 16.541 506.208 ;
      RECT 0.048 506.88 16.541 506.976 ;
      RECT 0.048 507.648 16.541 507.744 ;
      RECT 0.048 508.416 16.541 508.512 ;
      RECT 0.048 509.184 16.541 509.28 ;
      RECT 0.048 509.952 16.541 510.048 ;
      RECT 0.048 510.72 16.541 510.816 ;
      RECT 0.048 511.488 16.541 511.584 ;
      RECT 0.048 512.256 16.541 512.352 ;
      RECT 0.048 513.024 16.541 513.12 ;
      RECT 0.048 513.792 16.541 513.888 ;
      RECT 0.048 514.56 16.541 514.656 ;
      RECT 0.048 515.328 16.541 515.424 ;
      RECT 0.048 516.096 16.541 516.192 ;
      RECT 0.048 516.864 16.541 516.96 ;
      RECT 0.048 517.632 16.541 517.728 ;
      RECT 0.048 518.4 16.541 518.496 ;
      RECT 0.048 519.168 16.541 519.264 ;
      RECT 0.048 519.936 16.541 520.032 ;
      RECT 0.048 520.704 16.541 520.8 ;
      RECT 0.048 521.472 16.541 521.568 ;
      RECT 0.048 522.24 16.541 522.336 ;
      RECT 0.048 523.008 16.541 523.104 ;
      RECT 0.048 523.776 16.541 523.872 ;
      RECT 0.048 524.544 16.541 524.64 ;
      RECT 0.048 525.312 16.541 525.408 ;
      RECT 0.048 526.08 16.541 526.176 ;
      RECT 0.048 526.848 16.541 526.944 ;
      RECT 0.048 527.616 16.541 527.712 ;
      RECT 0.048 528.384 16.541 528.48 ;
      RECT 0.048 529.152 16.541 529.248 ;
      RECT 0.048 529.92 16.541 530.016 ;
      RECT 0.048 530.688 16.541 530.784 ;
      RECT 0.048 531.456 16.541 531.552 ;
      RECT 0.048 532.224 16.541 532.32 ;
      RECT 0.048 532.992 16.541 533.088 ;
      RECT 0.048 533.76 16.541 533.856 ;
      RECT 0.048 534.528 16.541 534.624 ;
      RECT 0.048 535.296 16.541 535.392 ;
      RECT 0.048 536.064 16.541 536.16 ;
      RECT 0.048 536.832 16.541 536.928 ;
      RECT 0.048 537.6 16.541 537.696 ;
      RECT 0.048 538.368 16.541 538.464 ;
      RECT 0.048 539.136 16.541 539.232 ;
      RECT 0.048 539.904 16.541 540 ;
      RECT 0.048 540.672 16.541 540.768 ;
      RECT 0.048 541.44 16.541 541.536 ;
      RECT 0.048 542.208 16.541 542.304 ;
      RECT 0.048 542.976 16.541 543.072 ;
      RECT 0.048 543.744 16.541 543.84 ;
      RECT 0.048 544.512 16.541 544.608 ;
      RECT 0.048 545.28 16.541 545.376 ;
      RECT 0.048 546.048 16.541 546.144 ;
      RECT 0.048 546.816 16.541 546.912 ;
      RECT 0.048 547.584 16.541 547.68 ;
      RECT 0.048 548.352 16.541 548.448 ;
      RECT 0.048 549.12 16.541 549.216 ;
      RECT 0.048 549.888 16.541 549.984 ;
      RECT 0.048 550.656 16.541 550.752 ;
      RECT 0.048 551.424 16.541 551.52 ;
      RECT 0.048 552.192 16.541 552.288 ;
      RECT 0.048 552.96 16.541 553.056 ;
      RECT 0.048 553.728 16.541 553.824 ;
      RECT 0.048 554.496 16.541 554.592 ;
      RECT 0.048 555.264 16.541 555.36 ;
      RECT 0.048 556.032 16.541 556.128 ;
      RECT 0.048 556.8 16.541 556.896 ;
      RECT 0.048 557.568 16.541 557.664 ;
      RECT 0.048 558.336 16.541 558.432 ;
      RECT 0.048 559.104 16.541 559.2 ;
      RECT 0.048 559.872 16.541 559.968 ;
      RECT 0.048 560.64 16.541 560.736 ;
      RECT 0.048 561.408 16.541 561.504 ;
      RECT 0.048 562.176 16.541 562.272 ;
      RECT 0.048 562.944 16.541 563.04 ;
      RECT 0.048 563.712 16.541 563.808 ;
      RECT 0.048 564.48 16.541 564.576 ;
      RECT 0.048 565.248 16.541 565.344 ;
      RECT 0.048 566.016 16.541 566.112 ;
      RECT 0.048 566.784 16.541 566.88 ;
      RECT 0.048 567.552 16.541 567.648 ;
      RECT 0.048 568.32 16.541 568.416 ;
      RECT 0.048 569.088 16.541 569.184 ;
      RECT 0.048 569.856 16.541 569.952 ;
      RECT 0.048 570.624 16.541 570.72 ;
      RECT 0.048 571.392 16.541 571.488 ;
      RECT 0.048 572.16 16.541 572.256 ;
      RECT 0.048 572.928 16.541 573.024 ;
      RECT 0.048 573.696 16.541 573.792 ;
      RECT 0.048 574.464 16.541 574.56 ;
      RECT 0.048 575.232 16.541 575.328 ;
      RECT 0.048 576 16.541 576.096 ;
      RECT 0.048 576.768 16.541 576.864 ;
      RECT 0.048 577.536 16.541 577.632 ;
      RECT 0.048 578.304 16.541 578.4 ;
      RECT 0.048 579.072 16.541 579.168 ;
      RECT 0.048 579.84 16.541 579.936 ;
      RECT 0.048 580.608 16.541 580.704 ;
      RECT 0.048 581.376 16.541 581.472 ;
      RECT 0.048 582.144 16.541 582.24 ;
      RECT 0.048 582.912 16.541 583.008 ;
      RECT 0.048 583.68 16.541 583.776 ;
      RECT 0.048 584.448 16.541 584.544 ;
      RECT 0.048 585.216 16.541 585.312 ;
      RECT 0.048 585.984 16.541 586.08 ;
      RECT 0.048 586.752 16.541 586.848 ;
      RECT 0.048 587.52 16.541 587.616 ;
      RECT 0.048 588.288 16.541 588.384 ;
      RECT 0.048 589.056 16.541 589.152 ;
      RECT 0.048 589.824 16.541 589.92 ;
      RECT 0.048 590.592 16.541 590.688 ;
      RECT 0.048 591.36 16.541 591.456 ;
      RECT 0.048 592.128 16.541 592.224 ;
      RECT 0.048 592.896 16.541 592.992 ;
      RECT 0.048 593.664 16.541 593.76 ;
      RECT 0.048 594.432 16.541 594.528 ;
      RECT 0.048 595.2 16.541 595.296 ;
      RECT 0.048 595.968 16.541 596.064 ;
      RECT 0.048 596.736 16.541 596.832 ;
      RECT 0.048 597.504 16.541 597.6 ;
      RECT 0.048 598.272 16.541 598.368 ;
      RECT 0.048 599.04 16.541 599.136 ;
      RECT 0.048 599.808 16.541 599.904 ;
      RECT 0.048 600.576 16.541 600.672 ;
      RECT 0.048 601.344 16.541 601.44 ;
      RECT 0.048 602.112 16.541 602.208 ;
      RECT 0.048 602.88 16.541 602.976 ;
      RECT 0.048 603.648 16.541 603.744 ;
      RECT 0.048 604.416 16.541 604.512 ;
      RECT 0.048 605.184 16.541 605.28 ;
      RECT 0.048 605.952 16.541 606.048 ;
      RECT 0.048 606.72 16.541 606.816 ;
      RECT 0.048 607.488 16.541 607.584 ;
      RECT 0.048 608.256 16.541 608.352 ;
      RECT 0.048 609.024 16.541 609.12 ;
      RECT 0.048 609.792 16.541 609.888 ;
      RECT 0.048 610.56 16.541 610.656 ;
      RECT 0.048 611.328 16.541 611.424 ;
      RECT 0.048 612.096 16.541 612.192 ;
      RECT 0.048 612.864 16.541 612.96 ;
      RECT 0.048 613.632 16.541 613.728 ;
      RECT 0.048 614.4 16.541 614.496 ;
      RECT 0.048 615.168 16.541 615.264 ;
      RECT 0.048 615.936 16.541 616.032 ;
      RECT 0.048 616.704 16.541 616.8 ;
      RECT 0.048 617.472 16.541 617.568 ;
      RECT 0.048 618.24 16.541 618.336 ;
      RECT 0.048 619.008 16.541 619.104 ;
      RECT 0.048 619.776 16.541 619.872 ;
      RECT 0.048 620.544 16.541 620.64 ;
      RECT 0.048 621.312 16.541 621.408 ;
      RECT 0.048 622.08 16.541 622.176 ;
      RECT 0.048 622.848 16.541 622.944 ;
      RECT 0.048 623.616 16.541 623.712 ;
      RECT 0.048 624.384 16.541 624.48 ;
      RECT 0.048 625.152 16.541 625.248 ;
      RECT 0.048 625.92 16.541 626.016 ;
      RECT 0.048 626.688 16.541 626.784 ;
      RECT 0.048 627.456 16.541 627.552 ;
      RECT 0.048 628.224 16.541 628.32 ;
      RECT 0.048 628.992 16.541 629.088 ;
      RECT 0.048 629.76 16.541 629.856 ;
      RECT 0.048 630.528 16.541 630.624 ;
      RECT 0.048 631.296 16.541 631.392 ;
      RECT 0.048 632.064 16.541 632.16 ;
      RECT 0.048 632.832 16.541 632.928 ;
      RECT 0.048 633.6 16.541 633.696 ;
      RECT 0.048 634.368 16.541 634.464 ;
      RECT 0.048 635.136 16.541 635.232 ;
      RECT 0.048 635.904 16.541 636 ;
      RECT 0.048 636.672 16.541 636.768 ;
      RECT 0.048 637.44 16.541 637.536 ;
      RECT 0.048 638.208 16.541 638.304 ;
      RECT 0.048 638.976 16.541 639.072 ;
      RECT 0.048 639.744 16.541 639.84 ;
      RECT 0.048 640.512 16.541 640.608 ;
      RECT 0.048 641.28 16.541 641.376 ;
      RECT 0.048 642.048 16.541 642.144 ;
      RECT 0.048 642.816 16.541 642.912 ;
      RECT 0.048 643.584 16.541 643.68 ;
      RECT 0.048 644.352 16.541 644.448 ;
      RECT 0.048 645.12 16.541 645.216 ;
      RECT 0.048 645.888 16.541 645.984 ;
      RECT 0.048 646.656 16.541 646.752 ;
      RECT 0.048 647.424 16.541 647.52 ;
      RECT 0.048 648.192 16.541 648.288 ;
      RECT 0.048 648.96 16.541 649.056 ;
      RECT 0.048 649.728 16.541 649.824 ;
      RECT 0.048 650.496 16.541 650.592 ;
      RECT 0.048 651.264 16.541 651.36 ;
      RECT 0.048 652.032 16.541 652.128 ;
      RECT 0.048 652.8 16.541 652.896 ;
      RECT 0.048 653.568 16.541 653.664 ;
      RECT 0.048 654.336 16.541 654.432 ;
      RECT 0.048 655.104 16.541 655.2 ;
      RECT 0.048 655.872 16.541 655.968 ;
      RECT 0.048 656.64 16.541 656.736 ;
      RECT 0.048 657.408 16.541 657.504 ;
      RECT 0.048 658.176 16.541 658.272 ;
      RECT 0.048 658.944 16.541 659.04 ;
      RECT 0.048 659.712 16.541 659.808 ;
      RECT 0.048 660.48 16.541 660.576 ;
      RECT 0.048 661.248 16.541 661.344 ;
      RECT 0.048 662.016 16.541 662.112 ;
      RECT 0.048 662.784 16.541 662.88 ;
      RECT 0.048 663.552 16.541 663.648 ;
      RECT 0.048 664.32 16.541 664.416 ;
      RECT 0.048 665.088 16.541 665.184 ;
      RECT 0.048 665.856 16.541 665.952 ;
    END
  END VSS
  PIN VDD
    DIRECTION INOUT ;
    USE POWER ;
    PORT
      LAYER M4_m ;
      RECT 0.048 0.384 16.541 0.48 ;
      RECT 0.048 1.152 16.541 1.248 ;
      RECT 0.048 1.92 16.541 2.016 ;
      RECT 0.048 2.688 16.541 2.784 ;
      RECT 0.048 3.456 16.541 3.552 ;
      RECT 0.048 4.224 16.541 4.32 ;
      RECT 0.048 4.992 16.541 5.088 ;
      RECT 0.048 5.76 16.541 5.856 ;
      RECT 0.048 6.528 16.541 6.624 ;
      RECT 0.048 7.296 16.541 7.392 ;
      RECT 0.048 8.064 16.541 8.16 ;
      RECT 0.048 8.832 16.541 8.928 ;
      RECT 0.048 9.6 16.541 9.696 ;
      RECT 0.048 10.368 16.541 10.464 ;
      RECT 0.048 11.136 16.541 11.232 ;
      RECT 0.048 11.904 16.541 12 ;
      RECT 0.048 12.672 16.541 12.768 ;
      RECT 0.048 13.44 16.541 13.536 ;
      RECT 0.048 14.208 16.541 14.304 ;
      RECT 0.048 14.976 16.541 15.072 ;
      RECT 0.048 15.744 16.541 15.84 ;
      RECT 0.048 16.512 16.541 16.608 ;
      RECT 0.048 17.28 16.541 17.376 ;
      RECT 0.048 18.048 16.541 18.144 ;
      RECT 0.048 18.816 16.541 18.912 ;
      RECT 0.048 19.584 16.541 19.68 ;
      RECT 0.048 20.352 16.541 20.448 ;
      RECT 0.048 21.12 16.541 21.216 ;
      RECT 0.048 21.888 16.541 21.984 ;
      RECT 0.048 22.656 16.541 22.752 ;
      RECT 0.048 23.424 16.541 23.52 ;
      RECT 0.048 24.192 16.541 24.288 ;
      RECT 0.048 24.96 16.541 25.056 ;
      RECT 0.048 25.728 16.541 25.824 ;
      RECT 0.048 26.496 16.541 26.592 ;
      RECT 0.048 27.264 16.541 27.36 ;
      RECT 0.048 28.032 16.541 28.128 ;
      RECT 0.048 28.8 16.541 28.896 ;
      RECT 0.048 29.568 16.541 29.664 ;
      RECT 0.048 30.336 16.541 30.432 ;
      RECT 0.048 31.104 16.541 31.2 ;
      RECT 0.048 31.872 16.541 31.968 ;
      RECT 0.048 32.64 16.541 32.736 ;
      RECT 0.048 33.408 16.541 33.504 ;
      RECT 0.048 34.176 16.541 34.272 ;
      RECT 0.048 34.944 16.541 35.04 ;
      RECT 0.048 35.712 16.541 35.808 ;
      RECT 0.048 36.48 16.541 36.576 ;
      RECT 0.048 37.248 16.541 37.344 ;
      RECT 0.048 38.016 16.541 38.112 ;
      RECT 0.048 38.784 16.541 38.88 ;
      RECT 0.048 39.552 16.541 39.648 ;
      RECT 0.048 40.32 16.541 40.416 ;
      RECT 0.048 41.088 16.541 41.184 ;
      RECT 0.048 41.856 16.541 41.952 ;
      RECT 0.048 42.624 16.541 42.72 ;
      RECT 0.048 43.392 16.541 43.488 ;
      RECT 0.048 44.16 16.541 44.256 ;
      RECT 0.048 44.928 16.541 45.024 ;
      RECT 0.048 45.696 16.541 45.792 ;
      RECT 0.048 46.464 16.541 46.56 ;
      RECT 0.048 47.232 16.541 47.328 ;
      RECT 0.048 48 16.541 48.096 ;
      RECT 0.048 48.768 16.541 48.864 ;
      RECT 0.048 49.536 16.541 49.632 ;
      RECT 0.048 50.304 16.541 50.4 ;
      RECT 0.048 51.072 16.541 51.168 ;
      RECT 0.048 51.84 16.541 51.936 ;
      RECT 0.048 52.608 16.541 52.704 ;
      RECT 0.048 53.376 16.541 53.472 ;
      RECT 0.048 54.144 16.541 54.24 ;
      RECT 0.048 54.912 16.541 55.008 ;
      RECT 0.048 55.68 16.541 55.776 ;
      RECT 0.048 56.448 16.541 56.544 ;
      RECT 0.048 57.216 16.541 57.312 ;
      RECT 0.048 57.984 16.541 58.08 ;
      RECT 0.048 58.752 16.541 58.848 ;
      RECT 0.048 59.52 16.541 59.616 ;
      RECT 0.048 60.288 16.541 60.384 ;
      RECT 0.048 61.056 16.541 61.152 ;
      RECT 0.048 61.824 16.541 61.92 ;
      RECT 0.048 62.592 16.541 62.688 ;
      RECT 0.048 63.36 16.541 63.456 ;
      RECT 0.048 64.128 16.541 64.224 ;
      RECT 0.048 64.896 16.541 64.992 ;
      RECT 0.048 65.664 16.541 65.76 ;
      RECT 0.048 66.432 16.541 66.528 ;
      RECT 0.048 67.2 16.541 67.296 ;
      RECT 0.048 67.968 16.541 68.064 ;
      RECT 0.048 68.736 16.541 68.832 ;
      RECT 0.048 69.504 16.541 69.6 ;
      RECT 0.048 70.272 16.541 70.368 ;
      RECT 0.048 71.04 16.541 71.136 ;
      RECT 0.048 71.808 16.541 71.904 ;
      RECT 0.048 72.576 16.541 72.672 ;
      RECT 0.048 73.344 16.541 73.44 ;
      RECT 0.048 74.112 16.541 74.208 ;
      RECT 0.048 74.88 16.541 74.976 ;
      RECT 0.048 75.648 16.541 75.744 ;
      RECT 0.048 76.416 16.541 76.512 ;
      RECT 0.048 77.184 16.541 77.28 ;
      RECT 0.048 77.952 16.541 78.048 ;
      RECT 0.048 78.72 16.541 78.816 ;
      RECT 0.048 79.488 16.541 79.584 ;
      RECT 0.048 80.256 16.541 80.352 ;
      RECT 0.048 81.024 16.541 81.12 ;
      RECT 0.048 81.792 16.541 81.888 ;
      RECT 0.048 82.56 16.541 82.656 ;
      RECT 0.048 83.328 16.541 83.424 ;
      RECT 0.048 84.096 16.541 84.192 ;
      RECT 0.048 84.864 16.541 84.96 ;
      RECT 0.048 85.632 16.541 85.728 ;
      RECT 0.048 86.4 16.541 86.496 ;
      RECT 0.048 87.168 16.541 87.264 ;
      RECT 0.048 87.936 16.541 88.032 ;
      RECT 0.048 88.704 16.541 88.8 ;
      RECT 0.048 89.472 16.541 89.568 ;
      RECT 0.048 90.24 16.541 90.336 ;
      RECT 0.048 91.008 16.541 91.104 ;
      RECT 0.048 91.776 16.541 91.872 ;
      RECT 0.048 92.544 16.541 92.64 ;
      RECT 0.048 93.312 16.541 93.408 ;
      RECT 0.048 94.08 16.541 94.176 ;
      RECT 0.048 94.848 16.541 94.944 ;
      RECT 0.048 95.616 16.541 95.712 ;
      RECT 0.048 96.384 16.541 96.48 ;
      RECT 0.048 97.152 16.541 97.248 ;
      RECT 0.048 97.92 16.541 98.016 ;
      RECT 0.048 98.688 16.541 98.784 ;
      RECT 0.048 99.456 16.541 99.552 ;
      RECT 0.048 100.224 16.541 100.32 ;
      RECT 0.048 100.992 16.541 101.088 ;
      RECT 0.048 101.76 16.541 101.856 ;
      RECT 0.048 102.528 16.541 102.624 ;
      RECT 0.048 103.296 16.541 103.392 ;
      RECT 0.048 104.064 16.541 104.16 ;
      RECT 0.048 104.832 16.541 104.928 ;
      RECT 0.048 105.6 16.541 105.696 ;
      RECT 0.048 106.368 16.541 106.464 ;
      RECT 0.048 107.136 16.541 107.232 ;
      RECT 0.048 107.904 16.541 108 ;
      RECT 0.048 108.672 16.541 108.768 ;
      RECT 0.048 109.44 16.541 109.536 ;
      RECT 0.048 110.208 16.541 110.304 ;
      RECT 0.048 110.976 16.541 111.072 ;
      RECT 0.048 111.744 16.541 111.84 ;
      RECT 0.048 112.512 16.541 112.608 ;
      RECT 0.048 113.28 16.541 113.376 ;
      RECT 0.048 114.048 16.541 114.144 ;
      RECT 0.048 114.816 16.541 114.912 ;
      RECT 0.048 115.584 16.541 115.68 ;
      RECT 0.048 116.352 16.541 116.448 ;
      RECT 0.048 117.12 16.541 117.216 ;
      RECT 0.048 117.888 16.541 117.984 ;
      RECT 0.048 118.656 16.541 118.752 ;
      RECT 0.048 119.424 16.541 119.52 ;
      RECT 0.048 120.192 16.541 120.288 ;
      RECT 0.048 120.96 16.541 121.056 ;
      RECT 0.048 121.728 16.541 121.824 ;
      RECT 0.048 122.496 16.541 122.592 ;
      RECT 0.048 123.264 16.541 123.36 ;
      RECT 0.048 124.032 16.541 124.128 ;
      RECT 0.048 124.8 16.541 124.896 ;
      RECT 0.048 125.568 16.541 125.664 ;
      RECT 0.048 126.336 16.541 126.432 ;
      RECT 0.048 127.104 16.541 127.2 ;
      RECT 0.048 127.872 16.541 127.968 ;
      RECT 0.048 128.64 16.541 128.736 ;
      RECT 0.048 129.408 16.541 129.504 ;
      RECT 0.048 130.176 16.541 130.272 ;
      RECT 0.048 130.944 16.541 131.04 ;
      RECT 0.048 131.712 16.541 131.808 ;
      RECT 0.048 132.48 16.541 132.576 ;
      RECT 0.048 133.248 16.541 133.344 ;
      RECT 0.048 134.016 16.541 134.112 ;
      RECT 0.048 134.784 16.541 134.88 ;
      RECT 0.048 135.552 16.541 135.648 ;
      RECT 0.048 136.32 16.541 136.416 ;
      RECT 0.048 137.088 16.541 137.184 ;
      RECT 0.048 137.856 16.541 137.952 ;
      RECT 0.048 138.624 16.541 138.72 ;
      RECT 0.048 139.392 16.541 139.488 ;
      RECT 0.048 140.16 16.541 140.256 ;
      RECT 0.048 140.928 16.541 141.024 ;
      RECT 0.048 141.696 16.541 141.792 ;
      RECT 0.048 142.464 16.541 142.56 ;
      RECT 0.048 143.232 16.541 143.328 ;
      RECT 0.048 144 16.541 144.096 ;
      RECT 0.048 144.768 16.541 144.864 ;
      RECT 0.048 145.536 16.541 145.632 ;
      RECT 0.048 146.304 16.541 146.4 ;
      RECT 0.048 147.072 16.541 147.168 ;
      RECT 0.048 147.84 16.541 147.936 ;
      RECT 0.048 148.608 16.541 148.704 ;
      RECT 0.048 149.376 16.541 149.472 ;
      RECT 0.048 150.144 16.541 150.24 ;
      RECT 0.048 150.912 16.541 151.008 ;
      RECT 0.048 151.68 16.541 151.776 ;
      RECT 0.048 152.448 16.541 152.544 ;
      RECT 0.048 153.216 16.541 153.312 ;
      RECT 0.048 153.984 16.541 154.08 ;
      RECT 0.048 154.752 16.541 154.848 ;
      RECT 0.048 155.52 16.541 155.616 ;
      RECT 0.048 156.288 16.541 156.384 ;
      RECT 0.048 157.056 16.541 157.152 ;
      RECT 0.048 157.824 16.541 157.92 ;
      RECT 0.048 158.592 16.541 158.688 ;
      RECT 0.048 159.36 16.541 159.456 ;
      RECT 0.048 160.128 16.541 160.224 ;
      RECT 0.048 160.896 16.541 160.992 ;
      RECT 0.048 161.664 16.541 161.76 ;
      RECT 0.048 162.432 16.541 162.528 ;
      RECT 0.048 163.2 16.541 163.296 ;
      RECT 0.048 163.968 16.541 164.064 ;
      RECT 0.048 164.736 16.541 164.832 ;
      RECT 0.048 165.504 16.541 165.6 ;
      RECT 0.048 166.272 16.541 166.368 ;
      RECT 0.048 167.04 16.541 167.136 ;
      RECT 0.048 167.808 16.541 167.904 ;
      RECT 0.048 168.576 16.541 168.672 ;
      RECT 0.048 169.344 16.541 169.44 ;
      RECT 0.048 170.112 16.541 170.208 ;
      RECT 0.048 170.88 16.541 170.976 ;
      RECT 0.048 171.648 16.541 171.744 ;
      RECT 0.048 172.416 16.541 172.512 ;
      RECT 0.048 173.184 16.541 173.28 ;
      RECT 0.048 173.952 16.541 174.048 ;
      RECT 0.048 174.72 16.541 174.816 ;
      RECT 0.048 175.488 16.541 175.584 ;
      RECT 0.048 176.256 16.541 176.352 ;
      RECT 0.048 177.024 16.541 177.12 ;
      RECT 0.048 177.792 16.541 177.888 ;
      RECT 0.048 178.56 16.541 178.656 ;
      RECT 0.048 179.328 16.541 179.424 ;
      RECT 0.048 180.096 16.541 180.192 ;
      RECT 0.048 180.864 16.541 180.96 ;
      RECT 0.048 181.632 16.541 181.728 ;
      RECT 0.048 182.4 16.541 182.496 ;
      RECT 0.048 183.168 16.541 183.264 ;
      RECT 0.048 183.936 16.541 184.032 ;
      RECT 0.048 184.704 16.541 184.8 ;
      RECT 0.048 185.472 16.541 185.568 ;
      RECT 0.048 186.24 16.541 186.336 ;
      RECT 0.048 187.008 16.541 187.104 ;
      RECT 0.048 187.776 16.541 187.872 ;
      RECT 0.048 188.544 16.541 188.64 ;
      RECT 0.048 189.312 16.541 189.408 ;
      RECT 0.048 190.08 16.541 190.176 ;
      RECT 0.048 190.848 16.541 190.944 ;
      RECT 0.048 191.616 16.541 191.712 ;
      RECT 0.048 192.384 16.541 192.48 ;
      RECT 0.048 193.152 16.541 193.248 ;
      RECT 0.048 193.92 16.541 194.016 ;
      RECT 0.048 194.688 16.541 194.784 ;
      RECT 0.048 195.456 16.541 195.552 ;
      RECT 0.048 196.224 16.541 196.32 ;
      RECT 0.048 196.992 16.541 197.088 ;
      RECT 0.048 197.76 16.541 197.856 ;
      RECT 0.048 198.528 16.541 198.624 ;
      RECT 0.048 199.296 16.541 199.392 ;
      RECT 0.048 200.064 16.541 200.16 ;
      RECT 0.048 200.832 16.541 200.928 ;
      RECT 0.048 201.6 16.541 201.696 ;
      RECT 0.048 202.368 16.541 202.464 ;
      RECT 0.048 203.136 16.541 203.232 ;
      RECT 0.048 203.904 16.541 204 ;
      RECT 0.048 204.672 16.541 204.768 ;
      RECT 0.048 205.44 16.541 205.536 ;
      RECT 0.048 206.208 16.541 206.304 ;
      RECT 0.048 206.976 16.541 207.072 ;
      RECT 0.048 207.744 16.541 207.84 ;
      RECT 0.048 208.512 16.541 208.608 ;
      RECT 0.048 209.28 16.541 209.376 ;
      RECT 0.048 210.048 16.541 210.144 ;
      RECT 0.048 210.816 16.541 210.912 ;
      RECT 0.048 211.584 16.541 211.68 ;
      RECT 0.048 212.352 16.541 212.448 ;
      RECT 0.048 213.12 16.541 213.216 ;
      RECT 0.048 213.888 16.541 213.984 ;
      RECT 0.048 214.656 16.541 214.752 ;
      RECT 0.048 215.424 16.541 215.52 ;
      RECT 0.048 216.192 16.541 216.288 ;
      RECT 0.048 216.96 16.541 217.056 ;
      RECT 0.048 217.728 16.541 217.824 ;
      RECT 0.048 218.496 16.541 218.592 ;
      RECT 0.048 219.264 16.541 219.36 ;
      RECT 0.048 220.032 16.541 220.128 ;
      RECT 0.048 220.8 16.541 220.896 ;
      RECT 0.048 221.568 16.541 221.664 ;
      RECT 0.048 222.336 16.541 222.432 ;
      RECT 0.048 223.104 16.541 223.2 ;
      RECT 0.048 223.872 16.541 223.968 ;
      RECT 0.048 224.64 16.541 224.736 ;
      RECT 0.048 225.408 16.541 225.504 ;
      RECT 0.048 226.176 16.541 226.272 ;
      RECT 0.048 226.944 16.541 227.04 ;
      RECT 0.048 227.712 16.541 227.808 ;
      RECT 0.048 228.48 16.541 228.576 ;
      RECT 0.048 229.248 16.541 229.344 ;
      RECT 0.048 230.016 16.541 230.112 ;
      RECT 0.048 230.784 16.541 230.88 ;
      RECT 0.048 231.552 16.541 231.648 ;
      RECT 0.048 232.32 16.541 232.416 ;
      RECT 0.048 233.088 16.541 233.184 ;
      RECT 0.048 233.856 16.541 233.952 ;
      RECT 0.048 234.624 16.541 234.72 ;
      RECT 0.048 235.392 16.541 235.488 ;
      RECT 0.048 236.16 16.541 236.256 ;
      RECT 0.048 236.928 16.541 237.024 ;
      RECT 0.048 237.696 16.541 237.792 ;
      RECT 0.048 238.464 16.541 238.56 ;
      RECT 0.048 239.232 16.541 239.328 ;
      RECT 0.048 240 16.541 240.096 ;
      RECT 0.048 240.768 16.541 240.864 ;
      RECT 0.048 241.536 16.541 241.632 ;
      RECT 0.048 242.304 16.541 242.4 ;
      RECT 0.048 243.072 16.541 243.168 ;
      RECT 0.048 243.84 16.541 243.936 ;
      RECT 0.048 244.608 16.541 244.704 ;
      RECT 0.048 245.376 16.541 245.472 ;
      RECT 0.048 246.144 16.541 246.24 ;
      RECT 0.048 246.912 16.541 247.008 ;
      RECT 0.048 247.68 16.541 247.776 ;
      RECT 0.048 248.448 16.541 248.544 ;
      RECT 0.048 249.216 16.541 249.312 ;
      RECT 0.048 249.984 16.541 250.08 ;
      RECT 0.048 250.752 16.541 250.848 ;
      RECT 0.048 251.52 16.541 251.616 ;
      RECT 0.048 252.288 16.541 252.384 ;
      RECT 0.048 253.056 16.541 253.152 ;
      RECT 0.048 253.824 16.541 253.92 ;
      RECT 0.048 254.592 16.541 254.688 ;
      RECT 0.048 255.36 16.541 255.456 ;
      RECT 0.048 256.128 16.541 256.224 ;
      RECT 0.048 256.896 16.541 256.992 ;
      RECT 0.048 257.664 16.541 257.76 ;
      RECT 0.048 258.432 16.541 258.528 ;
      RECT 0.048 259.2 16.541 259.296 ;
      RECT 0.048 259.968 16.541 260.064 ;
      RECT 0.048 260.736 16.541 260.832 ;
      RECT 0.048 261.504 16.541 261.6 ;
      RECT 0.048 262.272 16.541 262.368 ;
      RECT 0.048 263.04 16.541 263.136 ;
      RECT 0.048 263.808 16.541 263.904 ;
      RECT 0.048 264.576 16.541 264.672 ;
      RECT 0.048 265.344 16.541 265.44 ;
      RECT 0.048 266.112 16.541 266.208 ;
      RECT 0.048 266.88 16.541 266.976 ;
      RECT 0.048 267.648 16.541 267.744 ;
      RECT 0.048 268.416 16.541 268.512 ;
      RECT 0.048 269.184 16.541 269.28 ;
      RECT 0.048 269.952 16.541 270.048 ;
      RECT 0.048 270.72 16.541 270.816 ;
      RECT 0.048 271.488 16.541 271.584 ;
      RECT 0.048 272.256 16.541 272.352 ;
      RECT 0.048 273.024 16.541 273.12 ;
      RECT 0.048 273.792 16.541 273.888 ;
      RECT 0.048 274.56 16.541 274.656 ;
      RECT 0.048 275.328 16.541 275.424 ;
      RECT 0.048 276.096 16.541 276.192 ;
      RECT 0.048 276.864 16.541 276.96 ;
      RECT 0.048 277.632 16.541 277.728 ;
      RECT 0.048 278.4 16.541 278.496 ;
      RECT 0.048 279.168 16.541 279.264 ;
      RECT 0.048 279.936 16.541 280.032 ;
      RECT 0.048 280.704 16.541 280.8 ;
      RECT 0.048 281.472 16.541 281.568 ;
      RECT 0.048 282.24 16.541 282.336 ;
      RECT 0.048 283.008 16.541 283.104 ;
      RECT 0.048 283.776 16.541 283.872 ;
      RECT 0.048 284.544 16.541 284.64 ;
      RECT 0.048 285.312 16.541 285.408 ;
      RECT 0.048 286.08 16.541 286.176 ;
      RECT 0.048 286.848 16.541 286.944 ;
      RECT 0.048 287.616 16.541 287.712 ;
      RECT 0.048 288.384 16.541 288.48 ;
      RECT 0.048 289.152 16.541 289.248 ;
      RECT 0.048 289.92 16.541 290.016 ;
      RECT 0.048 290.688 16.541 290.784 ;
      RECT 0.048 291.456 16.541 291.552 ;
      RECT 0.048 292.224 16.541 292.32 ;
      RECT 0.048 292.992 16.541 293.088 ;
      RECT 0.048 293.76 16.541 293.856 ;
      RECT 0.048 294.528 16.541 294.624 ;
      RECT 0.048 295.296 16.541 295.392 ;
      RECT 0.048 296.064 16.541 296.16 ;
      RECT 0.048 296.832 16.541 296.928 ;
      RECT 0.048 297.6 16.541 297.696 ;
      RECT 0.048 298.368 16.541 298.464 ;
      RECT 0.048 299.136 16.541 299.232 ;
      RECT 0.048 299.904 16.541 300 ;
      RECT 0.048 300.672 16.541 300.768 ;
      RECT 0.048 301.44 16.541 301.536 ;
      RECT 0.048 302.208 16.541 302.304 ;
      RECT 0.048 302.976 16.541 303.072 ;
      RECT 0.048 303.744 16.541 303.84 ;
      RECT 0.048 304.512 16.541 304.608 ;
      RECT 0.048 305.28 16.541 305.376 ;
      RECT 0.048 306.048 16.541 306.144 ;
      RECT 0.048 306.816 16.541 306.912 ;
      RECT 0.048 307.584 16.541 307.68 ;
      RECT 0.048 308.352 16.541 308.448 ;
      RECT 0.048 309.12 16.541 309.216 ;
      RECT 0.048 309.888 16.541 309.984 ;
      RECT 0.048 310.656 16.541 310.752 ;
      RECT 0.048 311.424 16.541 311.52 ;
      RECT 0.048 312.192 16.541 312.288 ;
      RECT 0.048 312.96 16.541 313.056 ;
      RECT 0.048 313.728 16.541 313.824 ;
      RECT 0.048 314.496 16.541 314.592 ;
      RECT 0.048 315.264 16.541 315.36 ;
      RECT 0.048 316.032 16.541 316.128 ;
      RECT 0.048 316.8 16.541 316.896 ;
      RECT 0.048 317.568 16.541 317.664 ;
      RECT 0.048 318.336 16.541 318.432 ;
      RECT 0.048 319.104 16.541 319.2 ;
      RECT 0.048 319.872 16.541 319.968 ;
      RECT 0.048 320.64 16.541 320.736 ;
      RECT 0.048 321.408 16.541 321.504 ;
      RECT 0.048 322.176 16.541 322.272 ;
      RECT 0.048 322.944 16.541 323.04 ;
      RECT 0.048 323.712 16.541 323.808 ;
      RECT 0.048 324.48 16.541 324.576 ;
      RECT 0.048 325.248 16.541 325.344 ;
      RECT 0.048 326.016 16.541 326.112 ;
      RECT 0.048 326.784 16.541 326.88 ;
      RECT 0.048 327.552 16.541 327.648 ;
      RECT 0.048 328.32 16.541 328.416 ;
      RECT 0.048 329.088 16.541 329.184 ;
      RECT 0.048 329.856 16.541 329.952 ;
      RECT 0.048 330.624 16.541 330.72 ;
      RECT 0.048 331.392 16.541 331.488 ;
      RECT 0.048 332.16 16.541 332.256 ;
      RECT 0.048 332.928 16.541 333.024 ;
      RECT 0.048 333.696 16.541 333.792 ;
      RECT 0.048 334.464 16.541 334.56 ;
      RECT 0.048 335.232 16.541 335.328 ;
      RECT 0.048 336 16.541 336.096 ;
      RECT 0.048 336.768 16.541 336.864 ;
      RECT 0.048 337.536 16.541 337.632 ;
      RECT 0.048 338.304 16.541 338.4 ;
      RECT 0.048 339.072 16.541 339.168 ;
      RECT 0.048 339.84 16.541 339.936 ;
      RECT 0.048 340.608 16.541 340.704 ;
      RECT 0.048 341.376 16.541 341.472 ;
      RECT 0.048 342.144 16.541 342.24 ;
      RECT 0.048 342.912 16.541 343.008 ;
      RECT 0.048 343.68 16.541 343.776 ;
      RECT 0.048 344.448 16.541 344.544 ;
      RECT 0.048 345.216 16.541 345.312 ;
      RECT 0.048 345.984 16.541 346.08 ;
      RECT 0.048 346.752 16.541 346.848 ;
      RECT 0.048 347.52 16.541 347.616 ;
      RECT 0.048 348.288 16.541 348.384 ;
      RECT 0.048 349.056 16.541 349.152 ;
      RECT 0.048 349.824 16.541 349.92 ;
      RECT 0.048 350.592 16.541 350.688 ;
      RECT 0.048 351.36 16.541 351.456 ;
      RECT 0.048 352.128 16.541 352.224 ;
      RECT 0.048 352.896 16.541 352.992 ;
      RECT 0.048 353.664 16.541 353.76 ;
      RECT 0.048 354.432 16.541 354.528 ;
      RECT 0.048 355.2 16.541 355.296 ;
      RECT 0.048 355.968 16.541 356.064 ;
      RECT 0.048 356.736 16.541 356.832 ;
      RECT 0.048 357.504 16.541 357.6 ;
      RECT 0.048 358.272 16.541 358.368 ;
      RECT 0.048 359.04 16.541 359.136 ;
      RECT 0.048 359.808 16.541 359.904 ;
      RECT 0.048 360.576 16.541 360.672 ;
      RECT 0.048 361.344 16.541 361.44 ;
      RECT 0.048 362.112 16.541 362.208 ;
      RECT 0.048 362.88 16.541 362.976 ;
      RECT 0.048 363.648 16.541 363.744 ;
      RECT 0.048 364.416 16.541 364.512 ;
      RECT 0.048 365.184 16.541 365.28 ;
      RECT 0.048 365.952 16.541 366.048 ;
      RECT 0.048 366.72 16.541 366.816 ;
      RECT 0.048 367.488 16.541 367.584 ;
      RECT 0.048 368.256 16.541 368.352 ;
      RECT 0.048 369.024 16.541 369.12 ;
      RECT 0.048 369.792 16.541 369.888 ;
      RECT 0.048 370.56 16.541 370.656 ;
      RECT 0.048 371.328 16.541 371.424 ;
      RECT 0.048 372.096 16.541 372.192 ;
      RECT 0.048 372.864 16.541 372.96 ;
      RECT 0.048 373.632 16.541 373.728 ;
      RECT 0.048 374.4 16.541 374.496 ;
      RECT 0.048 375.168 16.541 375.264 ;
      RECT 0.048 375.936 16.541 376.032 ;
      RECT 0.048 376.704 16.541 376.8 ;
      RECT 0.048 377.472 16.541 377.568 ;
      RECT 0.048 378.24 16.541 378.336 ;
      RECT 0.048 379.008 16.541 379.104 ;
      RECT 0.048 379.776 16.541 379.872 ;
      RECT 0.048 380.544 16.541 380.64 ;
      RECT 0.048 381.312 16.541 381.408 ;
      RECT 0.048 382.08 16.541 382.176 ;
      RECT 0.048 382.848 16.541 382.944 ;
      RECT 0.048 383.616 16.541 383.712 ;
      RECT 0.048 384.384 16.541 384.48 ;
      RECT 0.048 385.152 16.541 385.248 ;
      RECT 0.048 385.92 16.541 386.016 ;
      RECT 0.048 386.688 16.541 386.784 ;
      RECT 0.048 387.456 16.541 387.552 ;
      RECT 0.048 388.224 16.541 388.32 ;
      RECT 0.048 388.992 16.541 389.088 ;
      RECT 0.048 389.76 16.541 389.856 ;
      RECT 0.048 390.528 16.541 390.624 ;
      RECT 0.048 391.296 16.541 391.392 ;
      RECT 0.048 392.064 16.541 392.16 ;
      RECT 0.048 392.832 16.541 392.928 ;
      RECT 0.048 393.6 16.541 393.696 ;
      RECT 0.048 394.368 16.541 394.464 ;
      RECT 0.048 395.136 16.541 395.232 ;
      RECT 0.048 395.904 16.541 396 ;
      RECT 0.048 396.672 16.541 396.768 ;
      RECT 0.048 397.44 16.541 397.536 ;
      RECT 0.048 398.208 16.541 398.304 ;
      RECT 0.048 398.976 16.541 399.072 ;
      RECT 0.048 399.744 16.541 399.84 ;
      RECT 0.048 400.512 16.541 400.608 ;
      RECT 0.048 401.28 16.541 401.376 ;
      RECT 0.048 402.048 16.541 402.144 ;
      RECT 0.048 402.816 16.541 402.912 ;
      RECT 0.048 403.584 16.541 403.68 ;
      RECT 0.048 404.352 16.541 404.448 ;
      RECT 0.048 405.12 16.541 405.216 ;
      RECT 0.048 405.888 16.541 405.984 ;
      RECT 0.048 406.656 16.541 406.752 ;
      RECT 0.048 407.424 16.541 407.52 ;
      RECT 0.048 408.192 16.541 408.288 ;
      RECT 0.048 408.96 16.541 409.056 ;
      RECT 0.048 409.728 16.541 409.824 ;
      RECT 0.048 410.496 16.541 410.592 ;
      RECT 0.048 411.264 16.541 411.36 ;
      RECT 0.048 412.032 16.541 412.128 ;
      RECT 0.048 412.8 16.541 412.896 ;
      RECT 0.048 413.568 16.541 413.664 ;
      RECT 0.048 414.336 16.541 414.432 ;
      RECT 0.048 415.104 16.541 415.2 ;
      RECT 0.048 415.872 16.541 415.968 ;
      RECT 0.048 416.64 16.541 416.736 ;
      RECT 0.048 417.408 16.541 417.504 ;
      RECT 0.048 418.176 16.541 418.272 ;
      RECT 0.048 418.944 16.541 419.04 ;
      RECT 0.048 419.712 16.541 419.808 ;
      RECT 0.048 420.48 16.541 420.576 ;
      RECT 0.048 421.248 16.541 421.344 ;
      RECT 0.048 422.016 16.541 422.112 ;
      RECT 0.048 422.784 16.541 422.88 ;
      RECT 0.048 423.552 16.541 423.648 ;
      RECT 0.048 424.32 16.541 424.416 ;
      RECT 0.048 425.088 16.541 425.184 ;
      RECT 0.048 425.856 16.541 425.952 ;
      RECT 0.048 426.624 16.541 426.72 ;
      RECT 0.048 427.392 16.541 427.488 ;
      RECT 0.048 428.16 16.541 428.256 ;
      RECT 0.048 428.928 16.541 429.024 ;
      RECT 0.048 429.696 16.541 429.792 ;
      RECT 0.048 430.464 16.541 430.56 ;
      RECT 0.048 431.232 16.541 431.328 ;
      RECT 0.048 432 16.541 432.096 ;
      RECT 0.048 432.768 16.541 432.864 ;
      RECT 0.048 433.536 16.541 433.632 ;
      RECT 0.048 434.304 16.541 434.4 ;
      RECT 0.048 435.072 16.541 435.168 ;
      RECT 0.048 435.84 16.541 435.936 ;
      RECT 0.048 436.608 16.541 436.704 ;
      RECT 0.048 437.376 16.541 437.472 ;
      RECT 0.048 438.144 16.541 438.24 ;
      RECT 0.048 438.912 16.541 439.008 ;
      RECT 0.048 439.68 16.541 439.776 ;
      RECT 0.048 440.448 16.541 440.544 ;
      RECT 0.048 441.216 16.541 441.312 ;
      RECT 0.048 441.984 16.541 442.08 ;
      RECT 0.048 442.752 16.541 442.848 ;
      RECT 0.048 443.52 16.541 443.616 ;
      RECT 0.048 444.288 16.541 444.384 ;
      RECT 0.048 445.056 16.541 445.152 ;
      RECT 0.048 445.824 16.541 445.92 ;
      RECT 0.048 446.592 16.541 446.688 ;
      RECT 0.048 447.36 16.541 447.456 ;
      RECT 0.048 448.128 16.541 448.224 ;
      RECT 0.048 448.896 16.541 448.992 ;
      RECT 0.048 449.664 16.541 449.76 ;
      RECT 0.048 450.432 16.541 450.528 ;
      RECT 0.048 451.2 16.541 451.296 ;
      RECT 0.048 451.968 16.541 452.064 ;
      RECT 0.048 452.736 16.541 452.832 ;
      RECT 0.048 453.504 16.541 453.6 ;
      RECT 0.048 454.272 16.541 454.368 ;
      RECT 0.048 455.04 16.541 455.136 ;
      RECT 0.048 455.808 16.541 455.904 ;
      RECT 0.048 456.576 16.541 456.672 ;
      RECT 0.048 457.344 16.541 457.44 ;
      RECT 0.048 458.112 16.541 458.208 ;
      RECT 0.048 458.88 16.541 458.976 ;
      RECT 0.048 459.648 16.541 459.744 ;
      RECT 0.048 460.416 16.541 460.512 ;
      RECT 0.048 461.184 16.541 461.28 ;
      RECT 0.048 461.952 16.541 462.048 ;
      RECT 0.048 462.72 16.541 462.816 ;
      RECT 0.048 463.488 16.541 463.584 ;
      RECT 0.048 464.256 16.541 464.352 ;
      RECT 0.048 465.024 16.541 465.12 ;
      RECT 0.048 465.792 16.541 465.888 ;
      RECT 0.048 466.56 16.541 466.656 ;
      RECT 0.048 467.328 16.541 467.424 ;
      RECT 0.048 468.096 16.541 468.192 ;
      RECT 0.048 468.864 16.541 468.96 ;
      RECT 0.048 469.632 16.541 469.728 ;
      RECT 0.048 470.4 16.541 470.496 ;
      RECT 0.048 471.168 16.541 471.264 ;
      RECT 0.048 471.936 16.541 472.032 ;
      RECT 0.048 472.704 16.541 472.8 ;
      RECT 0.048 473.472 16.541 473.568 ;
      RECT 0.048 474.24 16.541 474.336 ;
      RECT 0.048 475.008 16.541 475.104 ;
      RECT 0.048 475.776 16.541 475.872 ;
      RECT 0.048 476.544 16.541 476.64 ;
      RECT 0.048 477.312 16.541 477.408 ;
      RECT 0.048 478.08 16.541 478.176 ;
      RECT 0.048 478.848 16.541 478.944 ;
      RECT 0.048 479.616 16.541 479.712 ;
      RECT 0.048 480.384 16.541 480.48 ;
      RECT 0.048 481.152 16.541 481.248 ;
      RECT 0.048 481.92 16.541 482.016 ;
      RECT 0.048 482.688 16.541 482.784 ;
      RECT 0.048 483.456 16.541 483.552 ;
      RECT 0.048 484.224 16.541 484.32 ;
      RECT 0.048 484.992 16.541 485.088 ;
      RECT 0.048 485.76 16.541 485.856 ;
      RECT 0.048 486.528 16.541 486.624 ;
      RECT 0.048 487.296 16.541 487.392 ;
      RECT 0.048 488.064 16.541 488.16 ;
      RECT 0.048 488.832 16.541 488.928 ;
      RECT 0.048 489.6 16.541 489.696 ;
      RECT 0.048 490.368 16.541 490.464 ;
      RECT 0.048 491.136 16.541 491.232 ;
      RECT 0.048 491.904 16.541 492 ;
      RECT 0.048 492.672 16.541 492.768 ;
      RECT 0.048 493.44 16.541 493.536 ;
      RECT 0.048 494.208 16.541 494.304 ;
      RECT 0.048 494.976 16.541 495.072 ;
      RECT 0.048 495.744 16.541 495.84 ;
      RECT 0.048 496.512 16.541 496.608 ;
      RECT 0.048 497.28 16.541 497.376 ;
      RECT 0.048 498.048 16.541 498.144 ;
      RECT 0.048 498.816 16.541 498.912 ;
      RECT 0.048 499.584 16.541 499.68 ;
      RECT 0.048 500.352 16.541 500.448 ;
      RECT 0.048 501.12 16.541 501.216 ;
      RECT 0.048 501.888 16.541 501.984 ;
      RECT 0.048 502.656 16.541 502.752 ;
      RECT 0.048 503.424 16.541 503.52 ;
      RECT 0.048 504.192 16.541 504.288 ;
      RECT 0.048 504.96 16.541 505.056 ;
      RECT 0.048 505.728 16.541 505.824 ;
      RECT 0.048 506.496 16.541 506.592 ;
      RECT 0.048 507.264 16.541 507.36 ;
      RECT 0.048 508.032 16.541 508.128 ;
      RECT 0.048 508.8 16.541 508.896 ;
      RECT 0.048 509.568 16.541 509.664 ;
      RECT 0.048 510.336 16.541 510.432 ;
      RECT 0.048 511.104 16.541 511.2 ;
      RECT 0.048 511.872 16.541 511.968 ;
      RECT 0.048 512.64 16.541 512.736 ;
      RECT 0.048 513.408 16.541 513.504 ;
      RECT 0.048 514.176 16.541 514.272 ;
      RECT 0.048 514.944 16.541 515.04 ;
      RECT 0.048 515.712 16.541 515.808 ;
      RECT 0.048 516.48 16.541 516.576 ;
      RECT 0.048 517.248 16.541 517.344 ;
      RECT 0.048 518.016 16.541 518.112 ;
      RECT 0.048 518.784 16.541 518.88 ;
      RECT 0.048 519.552 16.541 519.648 ;
      RECT 0.048 520.32 16.541 520.416 ;
      RECT 0.048 521.088 16.541 521.184 ;
      RECT 0.048 521.856 16.541 521.952 ;
      RECT 0.048 522.624 16.541 522.72 ;
      RECT 0.048 523.392 16.541 523.488 ;
      RECT 0.048 524.16 16.541 524.256 ;
      RECT 0.048 524.928 16.541 525.024 ;
      RECT 0.048 525.696 16.541 525.792 ;
      RECT 0.048 526.464 16.541 526.56 ;
      RECT 0.048 527.232 16.541 527.328 ;
      RECT 0.048 528 16.541 528.096 ;
      RECT 0.048 528.768 16.541 528.864 ;
      RECT 0.048 529.536 16.541 529.632 ;
      RECT 0.048 530.304 16.541 530.4 ;
      RECT 0.048 531.072 16.541 531.168 ;
      RECT 0.048 531.84 16.541 531.936 ;
      RECT 0.048 532.608 16.541 532.704 ;
      RECT 0.048 533.376 16.541 533.472 ;
      RECT 0.048 534.144 16.541 534.24 ;
      RECT 0.048 534.912 16.541 535.008 ;
      RECT 0.048 535.68 16.541 535.776 ;
      RECT 0.048 536.448 16.541 536.544 ;
      RECT 0.048 537.216 16.541 537.312 ;
      RECT 0.048 537.984 16.541 538.08 ;
      RECT 0.048 538.752 16.541 538.848 ;
      RECT 0.048 539.52 16.541 539.616 ;
      RECT 0.048 540.288 16.541 540.384 ;
      RECT 0.048 541.056 16.541 541.152 ;
      RECT 0.048 541.824 16.541 541.92 ;
      RECT 0.048 542.592 16.541 542.688 ;
      RECT 0.048 543.36 16.541 543.456 ;
      RECT 0.048 544.128 16.541 544.224 ;
      RECT 0.048 544.896 16.541 544.992 ;
      RECT 0.048 545.664 16.541 545.76 ;
      RECT 0.048 546.432 16.541 546.528 ;
      RECT 0.048 547.2 16.541 547.296 ;
      RECT 0.048 547.968 16.541 548.064 ;
      RECT 0.048 548.736 16.541 548.832 ;
      RECT 0.048 549.504 16.541 549.6 ;
      RECT 0.048 550.272 16.541 550.368 ;
      RECT 0.048 551.04 16.541 551.136 ;
      RECT 0.048 551.808 16.541 551.904 ;
      RECT 0.048 552.576 16.541 552.672 ;
      RECT 0.048 553.344 16.541 553.44 ;
      RECT 0.048 554.112 16.541 554.208 ;
      RECT 0.048 554.88 16.541 554.976 ;
      RECT 0.048 555.648 16.541 555.744 ;
      RECT 0.048 556.416 16.541 556.512 ;
      RECT 0.048 557.184 16.541 557.28 ;
      RECT 0.048 557.952 16.541 558.048 ;
      RECT 0.048 558.72 16.541 558.816 ;
      RECT 0.048 559.488 16.541 559.584 ;
      RECT 0.048 560.256 16.541 560.352 ;
      RECT 0.048 561.024 16.541 561.12 ;
      RECT 0.048 561.792 16.541 561.888 ;
      RECT 0.048 562.56 16.541 562.656 ;
      RECT 0.048 563.328 16.541 563.424 ;
      RECT 0.048 564.096 16.541 564.192 ;
      RECT 0.048 564.864 16.541 564.96 ;
      RECT 0.048 565.632 16.541 565.728 ;
      RECT 0.048 566.4 16.541 566.496 ;
      RECT 0.048 567.168 16.541 567.264 ;
      RECT 0.048 567.936 16.541 568.032 ;
      RECT 0.048 568.704 16.541 568.8 ;
      RECT 0.048 569.472 16.541 569.568 ;
      RECT 0.048 570.24 16.541 570.336 ;
      RECT 0.048 571.008 16.541 571.104 ;
      RECT 0.048 571.776 16.541 571.872 ;
      RECT 0.048 572.544 16.541 572.64 ;
      RECT 0.048 573.312 16.541 573.408 ;
      RECT 0.048 574.08 16.541 574.176 ;
      RECT 0.048 574.848 16.541 574.944 ;
      RECT 0.048 575.616 16.541 575.712 ;
      RECT 0.048 576.384 16.541 576.48 ;
      RECT 0.048 577.152 16.541 577.248 ;
      RECT 0.048 577.92 16.541 578.016 ;
      RECT 0.048 578.688 16.541 578.784 ;
      RECT 0.048 579.456 16.541 579.552 ;
      RECT 0.048 580.224 16.541 580.32 ;
      RECT 0.048 580.992 16.541 581.088 ;
      RECT 0.048 581.76 16.541 581.856 ;
      RECT 0.048 582.528 16.541 582.624 ;
      RECT 0.048 583.296 16.541 583.392 ;
      RECT 0.048 584.064 16.541 584.16 ;
      RECT 0.048 584.832 16.541 584.928 ;
      RECT 0.048 585.6 16.541 585.696 ;
      RECT 0.048 586.368 16.541 586.464 ;
      RECT 0.048 587.136 16.541 587.232 ;
      RECT 0.048 587.904 16.541 588 ;
      RECT 0.048 588.672 16.541 588.768 ;
      RECT 0.048 589.44 16.541 589.536 ;
      RECT 0.048 590.208 16.541 590.304 ;
      RECT 0.048 590.976 16.541 591.072 ;
      RECT 0.048 591.744 16.541 591.84 ;
      RECT 0.048 592.512 16.541 592.608 ;
      RECT 0.048 593.28 16.541 593.376 ;
      RECT 0.048 594.048 16.541 594.144 ;
      RECT 0.048 594.816 16.541 594.912 ;
      RECT 0.048 595.584 16.541 595.68 ;
      RECT 0.048 596.352 16.541 596.448 ;
      RECT 0.048 597.12 16.541 597.216 ;
      RECT 0.048 597.888 16.541 597.984 ;
      RECT 0.048 598.656 16.541 598.752 ;
      RECT 0.048 599.424 16.541 599.52 ;
      RECT 0.048 600.192 16.541 600.288 ;
      RECT 0.048 600.96 16.541 601.056 ;
      RECT 0.048 601.728 16.541 601.824 ;
      RECT 0.048 602.496 16.541 602.592 ;
      RECT 0.048 603.264 16.541 603.36 ;
      RECT 0.048 604.032 16.541 604.128 ;
      RECT 0.048 604.8 16.541 604.896 ;
      RECT 0.048 605.568 16.541 605.664 ;
      RECT 0.048 606.336 16.541 606.432 ;
      RECT 0.048 607.104 16.541 607.2 ;
      RECT 0.048 607.872 16.541 607.968 ;
      RECT 0.048 608.64 16.541 608.736 ;
      RECT 0.048 609.408 16.541 609.504 ;
      RECT 0.048 610.176 16.541 610.272 ;
      RECT 0.048 610.944 16.541 611.04 ;
      RECT 0.048 611.712 16.541 611.808 ;
      RECT 0.048 612.48 16.541 612.576 ;
      RECT 0.048 613.248 16.541 613.344 ;
      RECT 0.048 614.016 16.541 614.112 ;
      RECT 0.048 614.784 16.541 614.88 ;
      RECT 0.048 615.552 16.541 615.648 ;
      RECT 0.048 616.32 16.541 616.416 ;
      RECT 0.048 617.088 16.541 617.184 ;
      RECT 0.048 617.856 16.541 617.952 ;
      RECT 0.048 618.624 16.541 618.72 ;
      RECT 0.048 619.392 16.541 619.488 ;
      RECT 0.048 620.16 16.541 620.256 ;
      RECT 0.048 620.928 16.541 621.024 ;
      RECT 0.048 621.696 16.541 621.792 ;
      RECT 0.048 622.464 16.541 622.56 ;
      RECT 0.048 623.232 16.541 623.328 ;
      RECT 0.048 624 16.541 624.096 ;
      RECT 0.048 624.768 16.541 624.864 ;
      RECT 0.048 625.536 16.541 625.632 ;
      RECT 0.048 626.304 16.541 626.4 ;
      RECT 0.048 627.072 16.541 627.168 ;
      RECT 0.048 627.84 16.541 627.936 ;
      RECT 0.048 628.608 16.541 628.704 ;
      RECT 0.048 629.376 16.541 629.472 ;
      RECT 0.048 630.144 16.541 630.24 ;
      RECT 0.048 630.912 16.541 631.008 ;
      RECT 0.048 631.68 16.541 631.776 ;
      RECT 0.048 632.448 16.541 632.544 ;
      RECT 0.048 633.216 16.541 633.312 ;
      RECT 0.048 633.984 16.541 634.08 ;
      RECT 0.048 634.752 16.541 634.848 ;
      RECT 0.048 635.52 16.541 635.616 ;
      RECT 0.048 636.288 16.541 636.384 ;
      RECT 0.048 637.056 16.541 637.152 ;
      RECT 0.048 637.824 16.541 637.92 ;
      RECT 0.048 638.592 16.541 638.688 ;
      RECT 0.048 639.36 16.541 639.456 ;
      RECT 0.048 640.128 16.541 640.224 ;
      RECT 0.048 640.896 16.541 640.992 ;
      RECT 0.048 641.664 16.541 641.76 ;
      RECT 0.048 642.432 16.541 642.528 ;
      RECT 0.048 643.2 16.541 643.296 ;
      RECT 0.048 643.968 16.541 644.064 ;
      RECT 0.048 644.736 16.541 644.832 ;
      RECT 0.048 645.504 16.541 645.6 ;
      RECT 0.048 646.272 16.541 646.368 ;
      RECT 0.048 647.04 16.541 647.136 ;
      RECT 0.048 647.808 16.541 647.904 ;
      RECT 0.048 648.576 16.541 648.672 ;
      RECT 0.048 649.344 16.541 649.44 ;
      RECT 0.048 650.112 16.541 650.208 ;
      RECT 0.048 650.88 16.541 650.976 ;
      RECT 0.048 651.648 16.541 651.744 ;
      RECT 0.048 652.416 16.541 652.512 ;
      RECT 0.048 653.184 16.541 653.28 ;
      RECT 0.048 653.952 16.541 654.048 ;
      RECT 0.048 654.72 16.541 654.816 ;
      RECT 0.048 655.488 16.541 655.584 ;
      RECT 0.048 656.256 16.541 656.352 ;
      RECT 0.048 657.024 16.541 657.12 ;
      RECT 0.048 657.792 16.541 657.888 ;
      RECT 0.048 658.56 16.541 658.656 ;
      RECT 0.048 659.328 16.541 659.424 ;
      RECT 0.048 660.096 16.541 660.192 ;
      RECT 0.048 660.864 16.541 660.96 ;
      RECT 0.048 661.632 16.541 661.728 ;
      RECT 0.048 662.4 16.541 662.496 ;
      RECT 0.048 663.168 16.541 663.264 ;
      RECT 0.048 663.936 16.541 664.032 ;
      RECT 0.048 664.704 16.541 664.8 ;
      RECT 0.048 665.472 16.541 665.568 ;
    END
  END VDD
  OBS
    LAYER M1_m ;
    RECT 0 0 16.589 666.144 ;
    LAYER M2_m ;
    RECT 0 0 16.589 666.144 ;
    LAYER M3_m ;
    RECT 0 0 16.589 666.144 ;
  END
END ht_asap7_rocketgemmini_cc_banks_0_ext_upper

END LIBRARY
